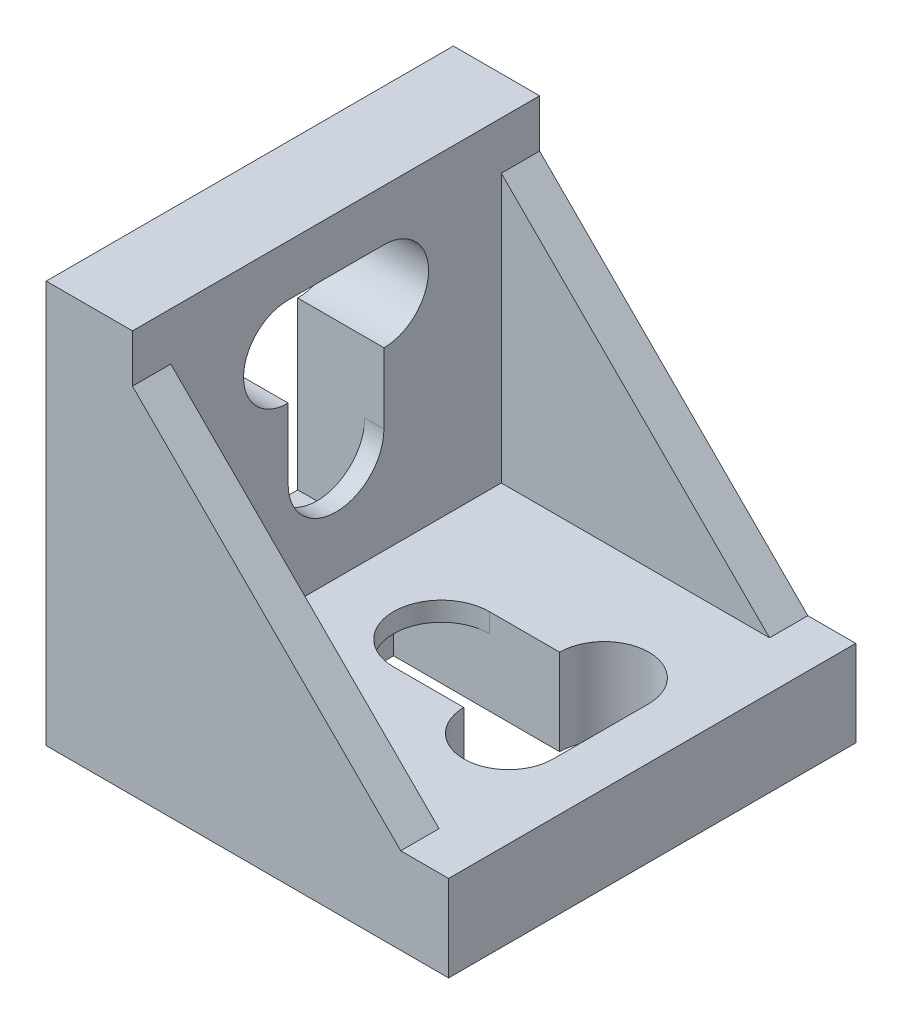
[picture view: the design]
ISO-10303-21;
HEADER;
FILE_DESCRIPTION(('STEP AP214'),'2;1');
FILE_NAME('part.step','',(''),(''),'','','');
FILE_SCHEMA(('AUTOMOTIVE_DESIGN { 1 0 10303 214 1 1 1 1 }'));
ENDSEC;
DATA;
#1=APPLICATION_CONTEXT('core data for automotive mechanical design processes');
#2=APPLICATION_PROTOCOL_DEFINITION('international standard','automotive_design',2000,#1);
#3=PRODUCT_CONTEXT('',#1,'mechanical');
#4=PRODUCT('Part','Part','',(#3));
#5=PRODUCT_RELATED_PRODUCT_CATEGORY('part','',(#4));
#6=PRODUCT_DEFINITION_FORMATION('','',#4);
#7=PRODUCT_DEFINITION_CONTEXT('part definition',#1,'design');
#8=PRODUCT_DEFINITION('design','',#6,#7);
#9=PRODUCT_DEFINITION_SHAPE('','',#8);
#10=(LENGTH_UNIT() NAMED_UNIT(*) SI_UNIT(.MILLI.,.METRE.));
#11=(NAMED_UNIT(*) PLANE_ANGLE_UNIT() SI_UNIT($,.RADIAN.));
#12=(NAMED_UNIT(*) SI_UNIT($,.STERADIAN.) SOLID_ANGLE_UNIT());
#13=UNCERTAINTY_MEASURE_WITH_UNIT(LENGTH_MEASURE(1.E-05),#10,'distance_accuracy_value','');
#14=(GEOMETRIC_REPRESENTATION_CONTEXT(3) GLOBAL_UNCERTAINTY_ASSIGNED_CONTEXT((#13)) GLOBAL_UNIT_ASSIGNED_CONTEXT((#10,
#11,#12)) REPRESENTATION_CONTEXT('',''));
#15=CARTESIAN_POINT('',(0.,0.,0.));
#16=DIRECTION('',(0.,0.,1.));
#17=DIRECTION('',(1.,0.,0.));
#18=AXIS2_PLACEMENT_3D('',#15,#16,#17);
#19=CARTESIAN_POINT('',(7.,-25.6172349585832,0.));
#20=DIRECTION('',(-1.,0.,0.));
#21=DIRECTION('',(0.,0.,1.));
#22=AXIS2_PLACEMENT_3D('',#19,#20,#21);
#23=PLANE('',#22);
#24=DIRECTION('',(0.,-1.,0.));
#25=VECTOR('',#24,1.);
#26=CARTESIAN_POINT('',(7.,-25.6172349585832,-18.25));
#27=LINE('',#26,#25);
#28=CARTESIAN_POINT('',(7.,40.,-18.25));
#29=VERTEX_POINT('',#28);
#30=CARTESIAN_POINT('',(7.,8.33885131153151,-18.25));
#31=VERTEX_POINT('',#30);
#32=EDGE_CURVE('E581',#29,#31,#27,.T.);
#33=ORIENTED_EDGE('',*,*,#32,.T.);
#34=DIRECTION('',(0.,0.,1.));
#35=VECTOR('',#34,1.);
#36=CARTESIAN_POINT('',(7.,8.33885131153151,-24.3860623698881));
#37=LINE('',#36,#35);
#38=CARTESIAN_POINT('',(7.,8.33885131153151,-8.75));
#39=VERTEX_POINT('',#38);
#40=EDGE_CURVE('E574',#31,#39,#37,.T.);
#41=ORIENTED_EDGE('',*,*,#40,.T.);
#42=DIRECTION('',(0.,1.,0.));
#43=VECTOR('',#42,1.);
#44=CARTESIAN_POINT('',(7.,-25.6172349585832,-8.75));
#45=LINE('',#44,#43);
#46=CARTESIAN_POINT('',(7.,25.5048094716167,-8.75));
#47=VERTEX_POINT('',#46);
#48=EDGE_CURVE('E578',#39,#47,#45,.T.);
#49=ORIENTED_EDGE('',*,*,#48,.T.);
#50=CARTESIAN_POINT('',(7.,32.,-5.));
#51=DIRECTION('',(-1.,0.,0.));
#52=DIRECTION('',(0.,0.,1.));
#53=AXIS2_PLACEMENT_3D('',#50,#51,#52);
#54=CIRCLE('',#53,7.5);
#55=CARTESIAN_POINT('',(7.,38.4951905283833,-8.75));
#56=VERTEX_POINT('',#55);
#57=EDGE_CURVE('E610',#56,#47,#54,.T.);
#58=ORIENTED_EDGE('',*,*,#57,.F.);
#59=DIRECTION('',(0.,-1.,0.));
#60=VECTOR('',#59,1.);
#61=CARTESIAN_POINT('',(7.,-25.6172349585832,-8.74999999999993));
#62=LINE('',#61,#60);
#63=CARTESIAN_POINT('',(7.,40.,-8.75));
#64=VERTEX_POINT('',#63);
#65=EDGE_CURVE('E809',#64,#56,#62,.T.);
#66=ORIENTED_EDGE('',*,*,#65,.F.);
#67=DIRECTION('',(0.,0.,1.));
#68=VECTOR('',#67,1.);
#69=CARTESIAN_POINT('',(7.,40.,0.));
#70=LINE('',#69,#68);
#71=EDGE_CURVE('E592',#29,#64,#70,.T.);
#72=ORIENTED_EDGE('',*,*,#71,.F.);
#73=EDGE_LOOP('',(#33,#41,#49,#58,#66,#72));
#74=FACE_BOUND('',#73,.T.);
#75=ADVANCED_FACE('F35',(#74),#23,.T.);
#76=CARTESIAN_POINT('',(7.,-25.6172349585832,-8.75));
#77=DIRECTION('',(0.,0.,1.));
#78=DIRECTION('',(1.,0.,0.));
#79=AXIS2_PLACEMENT_3D('',#76,#77,#78);
#80=PLANE('',#79);
#81=ORIENTED_EDGE('',*,*,#48,.F.);
#82=DIRECTION('',(0.707106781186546,0.707106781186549,0.));
#83=VECTOR('',#82,1.);
#84=CARTESIAN_POINT('',(-9.97804313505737,-8.63919182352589,-8.75));
#85=LINE('',#84,#83);
#86=CARTESIAN_POINT('',(0.,1.3388513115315,-8.75));
#87=VERTEX_POINT('',#86);
#88=EDGE_CURVE('E50',#39,#87,#85,.F.);
#89=ORIENTED_EDGE('',*,*,#88,.T.);
#90=DIRECTION('',(0.,1.,0.));
#91=VECTOR('',#90,1.);
#92=CARTESIAN_POINT('',(0.,-25.6172349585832,-8.75));
#93=LINE('',#92,#91);
#94=CARTESIAN_POINT('',(0.,25.5048094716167,-8.75));
#95=VERTEX_POINT('',#94);
#96=EDGE_CURVE('E608',#87,#95,#93,.T.);
#97=ORIENTED_EDGE('',*,*,#96,.T.);
#98=DIRECTION('',(-1.,0.,0.));
#99=VECTOR('',#98,1.);
#100=CARTESIAN_POINT('',(7.,25.5048094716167,-8.75));
#101=LINE('',#100,#99);
#102=EDGE_CURVE('E586',#47,#95,#101,.T.);
#103=ORIENTED_EDGE('',*,*,#102,.F.);
#104=EDGE_LOOP('',(#81,#89,#97,#103));
#105=FACE_BOUND('',#104,.T.);
#106=ADVANCED_FACE('F584',(#105),#80,.F.);
#107=CARTESIAN_POINT('',(7.,-25.6172349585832,-18.25));
#108=DIRECTION('',(0.,0.,-1.));
#109=DIRECTION('',(0.,1.,0.));
#110=AXIS2_PLACEMENT_3D('',#107,#108,#109);
#111=PLANE('',#110);
#112=DIRECTION('',(-0.707106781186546,-0.707106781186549,0.));
#113=VECTOR('',#112,1.);
#114=CARTESIAN_POINT('',(-9.97804313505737,-8.63919182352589,-18.25));
#115=LINE('',#114,#113);
#116=CARTESIAN_POINT('',(0.,1.3388513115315,-18.25));
#117=VERTEX_POINT('',#116);
#118=EDGE_CURVE('E58',#117,#31,#115,.F.);
#119=ORIENTED_EDGE('',*,*,#118,.T.);
#120=ORIENTED_EDGE('',*,*,#32,.F.);
#121=DIRECTION('',(-1.,0.,0.));
#122=VECTOR('',#121,1.);
#123=CARTESIAN_POINT('',(7.,40.,-18.25));
#124=LINE('',#123,#122);
#125=CARTESIAN_POINT('',(0.,40.,-18.25));
#126=VERTEX_POINT('',#125);
#127=EDGE_CURVE('E613',#29,#126,#124,.T.);
#128=ORIENTED_EDGE('',*,*,#127,.T.);
#129=DIRECTION('',(0.,-1.,0.));
#130=VECTOR('',#129,1.);
#131=CARTESIAN_POINT('',(0.,-25.6172349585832,-18.25));
#132=LINE('',#131,#130);
#133=EDGE_CURVE('E606',#126,#117,#132,.T.);
#134=ORIENTED_EDGE('',*,*,#133,.T.);
#135=EDGE_LOOP('',(#119,#120,#128,#134));
#136=FACE_BOUND('',#135,.T.);
#137=ADVANCED_FACE('F824',(#136),#111,.F.);
#138=CARTESIAN_POINT('',(7.,-25.6172349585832,0.));
#139=DIRECTION('',(-1.,0.,0.));
#140=DIRECTION('',(0.,0.,-1.));
#141=AXIS2_PLACEMENT_3D('',#138,#139,#140);
#142=PLANE('',#141);
#143=DIRECTION('',(0.,1.,0.));
#144=VECTOR('',#143,1.);
#145=CARTESIAN_POINT('',(7.,-25.6172349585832,8.75));
#146=LINE('',#145,#144);
#147=CARTESIAN_POINT('',(7.,8.33885131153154,8.75));
#148=VERTEX_POINT('',#147);
#149=CARTESIAN_POINT('',(7.,25.5048094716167,8.75));
#150=VERTEX_POINT('',#149);
#151=EDGE_CURVE('E549',#148,#150,#146,.T.);
#152=ORIENTED_EDGE('',*,*,#151,.F.);
#153=DIRECTION('',(0.,0.,1.));
#154=VECTOR('',#153,1.);
#155=CARTESIAN_POINT('',(7.,8.33885131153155,2.61393763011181));
#156=LINE('',#155,#154);
#157=CARTESIAN_POINT('',(7.,8.33885131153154,18.25));
#158=VERTEX_POINT('',#157);
#159=EDGE_CURVE('E485',#148,#158,#156,.T.);
#160=ORIENTED_EDGE('',*,*,#159,.T.);
#161=DIRECTION('',(0.,-1.,0.));
#162=VECTOR('',#161,1.);
#163=CARTESIAN_POINT('',(7.,-25.6172349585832,18.25));
#164=LINE('',#163,#162);
#165=CARTESIAN_POINT('',(7.,40.,18.25));
#166=VERTEX_POINT('',#165);
#167=EDGE_CURVE('E565',#166,#158,#164,.T.);
#168=ORIENTED_EDGE('',*,*,#167,.F.);
#169=DIRECTION('',(0.,0.,-1.));
#170=VECTOR('',#169,1.);
#171=CARTESIAN_POINT('',(7.,40.,0.));
#172=LINE('',#171,#170);
#173=CARTESIAN_POINT('',(7.,40.,8.75));
#174=VERTEX_POINT('',#173);
#175=EDGE_CURVE('E787',#166,#174,#172,.T.);
#176=ORIENTED_EDGE('',*,*,#175,.T.);
#177=DIRECTION('',(0.,-1.,0.));
#178=VECTOR('',#177,1.);
#179=CARTESIAN_POINT('',(7.,-25.6172349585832,8.74999999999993));
#180=LINE('',#179,#178);
#181=CARTESIAN_POINT('',(7.,38.4951905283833,8.75));
#182=VERTEX_POINT('',#181);
#183=EDGE_CURVE('E790',#174,#182,#180,.T.);
#184=ORIENTED_EDGE('',*,*,#183,.T.);
#185=CARTESIAN_POINT('',(7.,32.,5.));
#186=DIRECTION('',(1.,0.,0.));
#187=DIRECTION('',(0.,0.,-1.));
#188=AXIS2_PLACEMENT_3D('',#185,#186,#187);
#189=CIRCLE('',#188,7.5);
#190=EDGE_CURVE('E564',#182,#150,#189,.T.);
#191=ORIENTED_EDGE('',*,*,#190,.T.);
#192=EDGE_LOOP('',(#152,#160,#168,#176,#184,#191));
#193=FACE_BOUND('',#192,.T.);
#194=ADVANCED_FACE('F559',(#193),#142,.T.);
#195=CARTESIAN_POINT('',(7.,-25.6172349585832,18.25));
#196=DIRECTION('',(0.,0.,-1.));
#197=DIRECTION('',(0.,1.,0.));
#198=AXIS2_PLACEMENT_3D('',#195,#196,#197);
#199=PLANE('',#198);
#200=ORIENTED_EDGE('',*,*,#167,.T.);
#201=DIRECTION('',(-0.707106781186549,-0.707106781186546,0.));
#202=VECTOR('',#201,1.);
#203=CARTESIAN_POINT('',(0.,1.33885131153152,18.25));
#204=LINE('',#203,#202);
#205=CARTESIAN_POINT('',(0.,1.33885131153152,18.25));
#206=VERTEX_POINT('',#205);
#207=EDGE_CURVE('E11',#158,#206,#204,.T.);
#208=ORIENTED_EDGE('',*,*,#207,.T.);
#209=DIRECTION('',(0.,-1.,0.));
#210=VECTOR('',#209,1.);
#211=CARTESIAN_POINT('',(0.,-25.6172349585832,18.25));
#212=LINE('',#211,#210);
#213=CARTESIAN_POINT('',(0.,40.,18.25));
#214=VERTEX_POINT('',#213);
#215=EDGE_CURVE('E795',#214,#206,#212,.T.);
#216=ORIENTED_EDGE('',*,*,#215,.F.);
#217=DIRECTION('',(-1.,0.,0.));
#218=VECTOR('',#217,1.);
#219=CARTESIAN_POINT('',(7.,40.,18.25));
#220=LINE('',#219,#218);
#221=EDGE_CURVE('E805',#166,#214,#220,.T.);
#222=ORIENTED_EDGE('',*,*,#221,.F.);
#223=EDGE_LOOP('',(#200,#208,#216,#222));
#224=FACE_BOUND('',#223,.T.);
#225=ADVANCED_FACE('F832',(#224),#199,.T.);
#226=CARTESIAN_POINT('',(7.,-25.6172349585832,8.75));
#227=DIRECTION('',(0.,0.,1.));
#228=DIRECTION('',(1.,0.,0.));
#229=AXIS2_PLACEMENT_3D('',#226,#227,#228);
#230=PLANE('',#229);
#231=DIRECTION('',(0.707106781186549,0.707106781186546,0.));
#232=VECTOR('',#231,1.);
#233=CARTESIAN_POINT('',(0.,1.33885131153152,8.75));
#234=LINE('',#233,#232);
#235=CARTESIAN_POINT('',(0.,1.33885131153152,8.75));
#236=VERTEX_POINT('',#235);
#237=EDGE_CURVE('E43',#236,#148,#234,.T.);
#238=ORIENTED_EDGE('',*,*,#237,.T.);
#239=ORIENTED_EDGE('',*,*,#151,.T.);
#240=DIRECTION('',(-1.,0.,0.));
#241=VECTOR('',#240,1.);
#242=CARTESIAN_POINT('',(7.,25.5048094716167,8.75));
#243=LINE('',#242,#241);
#244=CARTESIAN_POINT('',(0.,25.5048094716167,8.75));
#245=VERTEX_POINT('',#244);
#246=EDGE_CURVE('E792',#150,#245,#243,.T.);
#247=ORIENTED_EDGE('',*,*,#246,.T.);
#248=DIRECTION('',(0.,1.,0.));
#249=VECTOR('',#248,1.);
#250=CARTESIAN_POINT('',(0.,-25.6172349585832,8.75));
#251=LINE('',#250,#249);
#252=EDGE_CURVE('E552',#236,#245,#251,.T.);
#253=ORIENTED_EDGE('',*,*,#252,.F.);
#254=EDGE_LOOP('',(#238,#239,#247,#253));
#255=FACE_BOUND('',#254,.T.);
#256=ADVANCED_FACE('F547',(#255),#230,.T.);
#257=CARTESIAN_POINT('',(42.,0.,21.25));
#258=DIRECTION('',(0.,1.,0.));
#259=DIRECTION('',(-1.,0.,0.));
#260=AXIS2_PLACEMENT_3D('',#257,#258,#259);
#261=PLANE('',#260);
#262=DIRECTION('',(0.,0.,-1.));
#263=VECTOR('',#262,1.);
#264=CARTESIAN_POINT('',(8.11245787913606,0.,-4.9));
#265=LINE('',#264,#263);
#266=CARTESIAN_POINT('',(8.11245787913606,0.,4.9));
#267=VERTEX_POINT('',#266);
#268=CARTESIAN_POINT('',(8.11245787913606,0.,-4.9));
#269=VERTEX_POINT('',#268);
#270=EDGE_CURVE('E484',#267,#269,#265,.T.);
#271=ORIENTED_EDGE('',*,*,#270,.T.);
#272=DIRECTION('',(-1.,0.,0.));
#273=VECTOR('',#272,1.);
#274=CARTESIAN_POINT('',(6.11245787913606,0.,-4.9));
#275=LINE('',#274,#273);
#276=CARTESIAN_POINT('',(6.11245787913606,0.,-4.9));
#277=VERTEX_POINT('',#276);
#278=EDGE_CURVE('E457',#269,#277,#275,.T.);
#279=ORIENTED_EDGE('',*,*,#278,.T.);
#280=DIRECTION('',(0.,0.,1.));
#281=VECTOR('',#280,1.);
#282=CARTESIAN_POINT('',(6.11245787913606,0.,4.9));
#283=LINE('',#282,#281);
#284=CARTESIAN_POINT('',(6.11245787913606,0.,4.9));
#285=VERTEX_POINT('',#284);
#286=EDGE_CURVE('E473',#277,#285,#283,.T.);
#287=ORIENTED_EDGE('',*,*,#286,.T.);
#288=DIRECTION('',(1.,0.,0.));
#289=VECTOR('',#288,1.);
#290=CARTESIAN_POINT('',(8.11245787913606,0.,4.9));
#291=LINE('',#290,#289);
#292=EDGE_CURVE('E487',#285,#267,#291,.T.);
#293=ORIENTED_EDGE('',*,*,#292,.T.);
#294=EDGE_LOOP('',(#271,#279,#287,#293));
#295=FACE_BOUND('',#294,.T.);
#296=DIRECTION('',(0.,0.,-1.));
#297=VECTOR('',#296,1.);
#298=CARTESIAN_POINT('',(38.6562082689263,0.,4.9));
#299=LINE('',#298,#297);
#300=CARTESIAN_POINT('',(38.6562082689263,0.,4.9));
#301=VERTEX_POINT('',#300);
#302=CARTESIAN_POINT('',(38.6562082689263,0.,-4.9));
#303=VERTEX_POINT('',#302);
#304=EDGE_CURVE('E512',#301,#303,#299,.T.);
#305=ORIENTED_EDGE('',*,*,#304,.T.);
#306=DIRECTION('',(-1.,0.,0.));
#307=VECTOR('',#306,1.);
#308=CARTESIAN_POINT('',(38.6562082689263,0.,-4.9));
#309=LINE('',#308,#307);
#310=CARTESIAN_POINT('',(36.6562082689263,0.,-4.9));
#311=VERTEX_POINT('',#310);
#312=EDGE_CURVE('E462',#303,#311,#309,.T.);
#313=ORIENTED_EDGE('',*,*,#312,.T.);
#314=DIRECTION('',(0.,0.,-1.));
#315=VECTOR('',#314,1.);
#316=CARTESIAN_POINT('',(36.6562082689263,0.,-5.));
#317=LINE('',#316,#315);
#318=CARTESIAN_POINT('',(36.6562082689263,0.,-5.));
#319=VERTEX_POINT('',#318);
#320=EDGE_CURVE('E923',#311,#319,#317,.T.);
#321=ORIENTED_EDGE('',*,*,#320,.T.);
#322=CARTESIAN_POINT('',(32.,0.,-5.));
#323=DIRECTION('',(0.,1.,0.));
#324=DIRECTION('',(0.,0.,1.));
#325=AXIS2_PLACEMENT_3D('',#322,#323,#324);
#326=CIRCLE('',#325,4.65620826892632);
#327=CARTESIAN_POINT('',(27.3437917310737,0.,-5.));
#328=VERTEX_POINT('',#327);
#329=EDGE_CURVE('E918',#319,#328,#326,.T.);
#330=ORIENTED_EDGE('',*,*,#329,.T.);
#331=DIRECTION('',(-1.,0.,0.));
#332=VECTOR('',#331,1.);
#333=CARTESIAN_POINT('',(30.,0.,-5.));
#334=LINE('',#333,#332);
#335=CARTESIAN_POINT('',(10.,0.,-5.));
#336=VERTEX_POINT('',#335);
#337=EDGE_CURVE('E1839',#328,#336,#334,.T.);
#338=ORIENTED_EDGE('',*,*,#337,.T.);
#339=DIRECTION('',(0.,0.,1.));
#340=VECTOR('',#339,1.);
#341=CARTESIAN_POINT('',(10.,0.,-5.));
#342=LINE('',#341,#340);
#343=CARTESIAN_POINT('',(10.,0.,5.));
#344=VERTEX_POINT('',#343);
#345=EDGE_CURVE('E900',#336,#344,#342,.T.);
#346=ORIENTED_EDGE('',*,*,#345,.T.);
#347=DIRECTION('',(1.,0.,0.));
#348=VECTOR('',#347,1.);
#349=CARTESIAN_POINT('',(30.,0.,5.));
#350=LINE('',#349,#348);
#351=CARTESIAN_POINT('',(27.3437917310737,0.,5.));
#352=VERTEX_POINT('',#351);
#353=EDGE_CURVE('E1844',#344,#352,#350,.T.);
#354=ORIENTED_EDGE('',*,*,#353,.T.);
#355=CARTESIAN_POINT('',(32.,0.,5.));
#356=DIRECTION('',(0.,1.,0.));
#357=DIRECTION('',(0.,0.,1.));
#358=AXIS2_PLACEMENT_3D('',#355,#356,#357);
#359=CIRCLE('',#358,4.65620826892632);
#360=CARTESIAN_POINT('',(36.6562082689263,0.,5.));
#361=VERTEX_POINT('',#360);
#362=EDGE_CURVE('E926',#352,#361,#359,.T.);
#363=ORIENTED_EDGE('',*,*,#362,.T.);
#364=CARTESIAN_POINT('',(36.6562082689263,0.,4.9));
#365=VERTEX_POINT('',#364);
#366=EDGE_CURVE('E932',#361,#365,#317,.T.);
#367=ORIENTED_EDGE('',*,*,#366,.T.);
#368=DIRECTION('',(1.,0.,0.));
#369=VECTOR('',#368,1.);
#370=CARTESIAN_POINT('',(36.6562082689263,0.,4.9));
#371=LINE('',#370,#369);
#372=EDGE_CURVE('E500',#365,#301,#371,.T.);
#373=ORIENTED_EDGE('',*,*,#372,.T.);
#374=EDGE_LOOP('',(#305,#313,#321,#330,#338,#346,#354,#363,#367,#373));
#375=FACE_BOUND('',#374,.T.);
#376=DIRECTION('',(1.,0.,0.));
#377=VECTOR('',#376,1.);
#378=CARTESIAN_POINT('',(42.,0.,-21.25));
#379=LINE('',#378,#377);
#380=CARTESIAN_POINT('',(0.,0.,-21.25));
#381=VERTEX_POINT('',#380);
#382=CARTESIAN_POINT('',(42.,0.,-21.25));
#383=VERTEX_POINT('',#382);
#384=EDGE_CURVE('E682',#381,#383,#379,.T.);
#385=ORIENTED_EDGE('',*,*,#384,.T.);
#386=DIRECTION('',(0.,0.,-1.));
#387=VECTOR('',#386,1.);
#388=CARTESIAN_POINT('',(42.,0.,21.25));
#389=LINE('',#388,#387);
#390=CARTESIAN_POINT('',(42.,0.,21.25));
#391=VERTEX_POINT('',#390);
#392=EDGE_CURVE('E657',#391,#383,#389,.T.);
#393=ORIENTED_EDGE('',*,*,#392,.F.);
#394=DIRECTION('',(1.,0.,0.));
#395=VECTOR('',#394,1.);
#396=CARTESIAN_POINT('',(42.,0.,21.25));
#397=LINE('',#396,#395);
#398=CARTESIAN_POINT('',(0.,0.,21.25));
#399=VERTEX_POINT('',#398);
#400=EDGE_CURVE('E696',#399,#391,#397,.T.);
#401=ORIENTED_EDGE('',*,*,#400,.F.);
#402=DIRECTION('',(0.,0.,-1.));
#403=VECTOR('',#402,1.);
#404=CARTESIAN_POINT('',(0.,0.,21.25));
#405=LINE('',#404,#403);
#406=EDGE_CURVE('E653',#399,#381,#405,.T.);
#407=ORIENTED_EDGE('',*,*,#406,.T.);
#408=EDGE_LOOP('',(#385,#393,#401,#407));
#409=FACE_BOUND('',#408,.T.);
#410=DIRECTION('',(0.,0.,1.));
#411=VECTOR('',#410,1.);
#412=CARTESIAN_POINT('',(1.33885131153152,0.,-8.75));
#413=LINE('',#412,#411);
#414=CARTESIAN_POINT('',(1.33885131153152,0.,-18.25));
#415=VERTEX_POINT('',#414);
#416=CARTESIAN_POINT('',(1.33885131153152,0.,-8.75));
#417=VERTEX_POINT('',#416);
#418=EDGE_CURVE('E520',#415,#417,#413,.T.);
#419=ORIENTED_EDGE('',*,*,#418,.T.);
#420=DIRECTION('',(1.,0.,0.));
#421=VECTOR('',#420,1.);
#422=CARTESIAN_POINT('',(0.,0.,-8.75));
#423=LINE('',#422,#421);
#424=CARTESIAN_POINT('',(25.5048094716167,0.,-8.75));
#425=VERTEX_POINT('',#424);
#426=EDGE_CURVE('E858',#417,#425,#423,.T.);
#427=ORIENTED_EDGE('',*,*,#426,.T.);
#428=CARTESIAN_POINT('',(32.,0.,-5.));
#429=DIRECTION('',(0.,1.,0.));
#430=DIRECTION('',(0.,0.,1.));
#431=AXIS2_PLACEMENT_3D('',#428,#429,#430);
#432=CIRCLE('',#431,7.5);
#433=CARTESIAN_POINT('',(38.4951905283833,0.,-8.75));
#434=VERTEX_POINT('',#433);
#435=EDGE_CURVE('E887',#434,#425,#432,.T.);
#436=ORIENTED_EDGE('',*,*,#435,.F.);
#437=DIRECTION('',(-1.,0.,0.));
#438=VECTOR('',#437,1.);
#439=CARTESIAN_POINT('',(0.,0.,-8.74999999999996));
#440=LINE('',#439,#438);
#441=CARTESIAN_POINT('',(40.,0.,-8.75));
#442=VERTEX_POINT('',#441);
#443=EDGE_CURVE('E895',#442,#434,#440,.T.);
#444=ORIENTED_EDGE('',*,*,#443,.F.);
#445=DIRECTION('',(0.,0.,1.));
#446=VECTOR('',#445,1.);
#447=CARTESIAN_POINT('',(40.,0.,0.));
#448=LINE('',#447,#446);
#449=CARTESIAN_POINT('',(40.,0.,-18.25));
#450=VERTEX_POINT('',#449);
#451=EDGE_CURVE('E892',#450,#442,#448,.T.);
#452=ORIENTED_EDGE('',*,*,#451,.F.);
#453=DIRECTION('',(-1.,0.,0.));
#454=VECTOR('',#453,1.);
#455=CARTESIAN_POINT('',(0.,0.,-18.25));
#456=LINE('',#455,#454);
#457=EDGE_CURVE('E874',#450,#415,#456,.T.);
#458=ORIENTED_EDGE('',*,*,#457,.T.);
#459=EDGE_LOOP('',(#419,#427,#436,#444,#452,#458));
#460=FACE_BOUND('',#459,.T.);
#461=DIRECTION('',(1.,0.,0.));
#462=VECTOR('',#461,1.);
#463=CARTESIAN_POINT('',(0.,0.,8.75));
#464=LINE('',#463,#462);
#465=CARTESIAN_POINT('',(1.3388513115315,0.,8.75));
#466=VERTEX_POINT('',#465);
#467=CARTESIAN_POINT('',(25.5048094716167,0.,8.75));
#468=VERTEX_POINT('',#467);
#469=EDGE_CURVE('E1791',#466,#468,#464,.T.);
#470=ORIENTED_EDGE('',*,*,#469,.F.);
#471=DIRECTION('',(0.,0.,1.));
#472=VECTOR('',#471,1.);
#473=CARTESIAN_POINT('',(1.3388513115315,0.,21.25));
#474=LINE('',#473,#472);
#475=CARTESIAN_POINT('',(1.3388513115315,0.,18.25));
#476=VERTEX_POINT('',#475);
#477=EDGE_CURVE('E529',#466,#476,#474,.T.);
#478=ORIENTED_EDGE('',*,*,#477,.T.);
#479=DIRECTION('',(-1.,0.,0.));
#480=VECTOR('',#479,1.);
#481=CARTESIAN_POINT('',(0.,0.,18.25));
#482=LINE('',#481,#480);
#483=CARTESIAN_POINT('',(40.,0.,18.25));
#484=VERTEX_POINT('',#483);
#485=EDGE_CURVE('E1789',#484,#476,#482,.T.);
#486=ORIENTED_EDGE('',*,*,#485,.F.);
#487=DIRECTION('',(0.,0.,-1.));
#488=VECTOR('',#487,1.);
#489=CARTESIAN_POINT('',(40.,0.,0.));
#490=LINE('',#489,#488);
#491=CARTESIAN_POINT('',(40.,0.,8.75));
#492=VERTEX_POINT('',#491);
#493=EDGE_CURVE('E1786',#484,#492,#490,.T.);
#494=ORIENTED_EDGE('',*,*,#493,.T.);
#495=DIRECTION('',(-1.,0.,0.));
#496=VECTOR('',#495,1.);
#497=CARTESIAN_POINT('',(0.,0.,8.74999999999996));
#498=LINE('',#497,#496);
#499=CARTESIAN_POINT('',(38.4951905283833,0.,8.75));
#500=VERTEX_POINT('',#499);
#501=EDGE_CURVE('E1782',#492,#500,#498,.T.);
#502=ORIENTED_EDGE('',*,*,#501,.T.);
#503=CARTESIAN_POINT('',(32.,0.,5.));
#504=DIRECTION('',(0.,-1.,0.));
#505=DIRECTION('',(0.,0.,-1.));
#506=AXIS2_PLACEMENT_3D('',#503,#504,#505);
#507=CIRCLE('',#506,7.5);
#508=EDGE_CURVE('E1779',#500,#468,#507,.T.);
#509=ORIENTED_EDGE('',*,*,#508,.T.);
#510=EDGE_LOOP('',(#470,#478,#486,#494,#502,#509));
#511=FACE_BOUND('',#510,.T.);
#512=ADVANCED_FACE('F1053',(#295,#375,#409,#460,#511),#261,.F.);
#513=CARTESIAN_POINT('',(20.,42.,0.));
#514=DIRECTION('',(0.,-1.,0.));
#515=DIRECTION('',(1.,0.,0.));
#516=AXIS2_PLACEMENT_3D('',#513,#514,#515);
#517=CYLINDRICAL_SURFACE('',#516,5.);
#518=DIRECTION('',(0.,-1.,0.));
#519=VECTOR('',#518,1.);
#520=CARTESIAN_POINT('',(20.,42.,5.));
#521=LINE('',#520,#519);
#522=CARTESIAN_POINT('',(20.,9.,5.));
#523=VERTEX_POINT('',#522);
#524=CARTESIAN_POINT('',(20.,7.00000000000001,5.));
#525=VERTEX_POINT('',#524);
#526=EDGE_CURVE('E1843',#523,#525,#521,.T.);
#527=ORIENTED_EDGE('',*,*,#526,.T.);
#528=CARTESIAN_POINT('',(20.,7.00000000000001,0.));
#529=DIRECTION('',(0.,-1.,0.));
#530=DIRECTION('',(1.,0.,0.));
#531=AXIS2_PLACEMENT_3D('',#528,#529,#530);
#532=CIRCLE('',#531,5.);
#533=CARTESIAN_POINT('',(20.,7.00000000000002,-5.));
#534=VERTEX_POINT('',#533);
#535=EDGE_CURVE('E524',#525,#534,#532,.T.);
#536=ORIENTED_EDGE('',*,*,#535,.T.);
#537=DIRECTION('',(0.,-1.,0.));
#538=VECTOR('',#537,1.);
#539=CARTESIAN_POINT('',(20.,42.,-5.));
#540=LINE('',#539,#538);
#541=CARTESIAN_POINT('',(20.,9.00000000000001,-5.));
#542=VERTEX_POINT('',#541);
#543=EDGE_CURVE('E1847',#542,#534,#540,.T.);
#544=ORIENTED_EDGE('',*,*,#543,.F.);
#545=CARTESIAN_POINT('',(20.,9.,0.));
#546=DIRECTION('',(0.,-1.,0.));
#547=DIRECTION('',(0.,0.,-1.));
#548=AXIS2_PLACEMENT_3D('',#545,#546,#547);
#549=CIRCLE('',#548,5.);
#550=EDGE_CURVE('E1857',#542,#523,#549,.F.);
#551=ORIENTED_EDGE('',*,*,#550,.T.);
#552=EDGE_LOOP('',(#527,#536,#544,#551));
#553=FACE_BOUND('',#552,.T.);
#554=ADVANCED_FACE('F1118',(#553),#517,.F.);
#555=CARTESIAN_POINT('',(9.,9.,21.25));
#556=DIRECTION('',(0.,-1.,0.));
#557=DIRECTION('',(0.,0.,-1.));
#558=AXIS2_PLACEMENT_3D('',#555,#556,#557);
#559=PLANE('',#558);
#560=DIRECTION('',(0.,0.,-1.));
#561=VECTOR('',#560,1.);
#562=CARTESIAN_POINT('',(37.,9.,-17.25));
#563=LINE('',#562,#561);
#564=CARTESIAN_POINT('',(37.,9.,-17.25));
#565=VERTEX_POINT('',#564);
#566=CARTESIAN_POINT('',(37.,9.,-21.25));
#567=VERTEX_POINT('',#566);
#568=EDGE_CURVE('E709',#565,#567,#563,.T.);
#569=ORIENTED_EDGE('',*,*,#568,.F.);
#570=DIRECTION('',(1.,0.,0.));
#571=VECTOR('',#570,1.);
#572=CARTESIAN_POINT('',(37.,9.,-17.25));
#573=LINE('',#572,#571);
#574=CARTESIAN_POINT('',(9.,9.,-17.25));
#575=VERTEX_POINT('',#574);
#576=EDGE_CURVE('E719',#575,#565,#573,.T.);
#577=ORIENTED_EDGE('',*,*,#576,.F.);
#578=DIRECTION('',(0.,0.,-1.));
#579=VECTOR('',#578,1.);
#580=CARTESIAN_POINT('',(9.,9.,21.25));
#581=LINE('',#580,#579);
#582=CARTESIAN_POINT('',(9.,9.,17.25));
#583=VERTEX_POINT('',#582);
#584=EDGE_CURVE('E663',#583,#575,#581,.T.);
#585=ORIENTED_EDGE('',*,*,#584,.F.);
#586=DIRECTION('',(1.,0.,0.));
#587=VECTOR('',#586,1.);
#588=CARTESIAN_POINT('',(37.,9.,17.25));
#589=LINE('',#588,#587);
#590=CARTESIAN_POINT('',(37.,9.,17.25));
#591=VERTEX_POINT('',#590);
#592=EDGE_CURVE('E712',#583,#591,#589,.T.);
#593=ORIENTED_EDGE('',*,*,#592,.T.);
#594=DIRECTION('',(0.,0.,1.));
#595=VECTOR('',#594,1.);
#596=CARTESIAN_POINT('',(37.,9.,17.25));
#597=LINE('',#596,#595);
#598=CARTESIAN_POINT('',(37.,9.,21.25));
#599=VERTEX_POINT('',#598);
#600=EDGE_CURVE('E700',#591,#599,#597,.T.);
#601=ORIENTED_EDGE('',*,*,#600,.T.);
#602=DIRECTION('',(-1.,0.,0.));
#603=VECTOR('',#602,1.);
#604=CARTESIAN_POINT('',(9.,9.,21.25));
#605=LINE('',#604,#603);
#606=CARTESIAN_POINT('',(42.,9.,21.25));
#607=VERTEX_POINT('',#606);
#608=EDGE_CURVE('E691',#607,#599,#605,.T.);
#609=ORIENTED_EDGE('',*,*,#608,.F.);
#610=DIRECTION('',(0.,0.,-1.));
#611=VECTOR('',#610,1.);
#612=CARTESIAN_POINT('',(42.,9.,21.25));
#613=LINE('',#612,#611);
#614=CARTESIAN_POINT('',(42.,9.,-21.25));
#615=VERTEX_POINT('',#614);
#616=EDGE_CURVE('E660',#607,#615,#613,.T.);
#617=ORIENTED_EDGE('',*,*,#616,.T.);
#618=DIRECTION('',(-1.,0.,0.));
#619=VECTOR('',#618,1.);
#620=CARTESIAN_POINT('',(9.,9.,-21.25));
#621=LINE('',#620,#619);
#622=EDGE_CURVE('E678',#615,#567,#621,.T.);
#623=ORIENTED_EDGE('',*,*,#622,.T.);
#624=EDGE_LOOP('',(#569,#577,#585,#593,#601,#609,#617,#623));
#625=FACE_BOUND('',#624,.T.);
#626=CARTESIAN_POINT('',(32.,9.,-5.));
#627=DIRECTION('',(0.,-1.,0.));
#628=DIRECTION('',(0.,0.,-1.));
#629=AXIS2_PLACEMENT_3D('',#626,#627,#628);
#630=CIRCLE('',#629,4.65620826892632);
#631=CARTESIAN_POINT('',(36.6562082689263,9.,-5.));
#632=VERTEX_POINT('',#631);
#633=CARTESIAN_POINT('',(27.3437917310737,9.00000000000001,-5.));
#634=VERTEX_POINT('',#633);
#635=EDGE_CURVE('E1905',#632,#634,#630,.F.);
#636=ORIENTED_EDGE('',*,*,#635,.F.);
#637=DIRECTION('',(0.,0.,-1.));
#638=VECTOR('',#637,1.);
#639=CARTESIAN_POINT('',(36.6562082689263,9.,21.25));
#640=LINE('',#639,#638);
#641=CARTESIAN_POINT('',(36.6562082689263,9.,5.));
#642=VERTEX_POINT('',#641);
#643=EDGE_CURVE('E1832',#642,#632,#640,.T.);
#644=ORIENTED_EDGE('',*,*,#643,.F.);
#645=CARTESIAN_POINT('',(32.,9.,5.));
#646=DIRECTION('',(0.,-1.,0.));
#647=DIRECTION('',(0.,0.,-1.));
#648=AXIS2_PLACEMENT_3D('',#645,#646,#647);
#649=CIRCLE('',#648,4.65620826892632);
#650=CARTESIAN_POINT('',(27.3437917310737,9.00000000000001,5.));
#651=VERTEX_POINT('',#650);
#652=EDGE_CURVE('E1894',#651,#642,#649,.F.);
#653=ORIENTED_EDGE('',*,*,#652,.F.);
#654=DIRECTION('',(1.,0.,0.));
#655=VECTOR('',#654,1.);
#656=CARTESIAN_POINT('',(9.,9.,5.));
#657=LINE('',#656,#655);
#658=EDGE_CURVE('E1853',#523,#651,#657,.T.);
#659=ORIENTED_EDGE('',*,*,#658,.F.);
#660=ORIENTED_EDGE('',*,*,#550,.F.);
#661=DIRECTION('',(-1.,0.,0.));
#662=VECTOR('',#661,1.);
#663=CARTESIAN_POINT('',(9.,9.,-5.));
#664=LINE('',#663,#662);
#665=EDGE_CURVE('E1860',#634,#542,#664,.T.);
#666=ORIENTED_EDGE('',*,*,#665,.F.);
#667=EDGE_LOOP('',(#636,#644,#653,#659,#660,#666));
#668=FACE_BOUND('',#667,.T.);
#669=ADVANCED_FACE('F1093',(#625,#668),#559,.F.);
#670=CARTESIAN_POINT('',(30.,42.,-5.));
#671=DIRECTION('',(0.,0.,1.));
#672=DIRECTION('',(1.,0.,0.));
#673=AXIS2_PLACEMENT_3D('',#670,#671,#672);
#674=PLANE('',#673);
#675=DIRECTION('',(0.,-1.,0.));
#676=VECTOR('',#675,1.);
#677=CARTESIAN_POINT('',(10.,7.,-5.));
#678=LINE('',#677,#676);
#679=CARTESIAN_POINT('',(10.,7.,-5.));
#680=VERTEX_POINT('',#679);
#681=EDGE_CURVE('E915',#680,#336,#678,.T.);
#682=ORIENTED_EDGE('',*,*,#681,.T.);
#683=ORIENTED_EDGE('',*,*,#337,.F.);
#684=DIRECTION('',(0.,-1.,0.));
#685=VECTOR('',#684,1.);
#686=CARTESIAN_POINT('',(27.3437917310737,42.,-5.));
#687=LINE('',#686,#685);
#688=EDGE_CURVE('E1837',#634,#328,#687,.T.);
#689=ORIENTED_EDGE('',*,*,#688,.F.);
#690=ORIENTED_EDGE('',*,*,#665,.T.);
#691=ORIENTED_EDGE('',*,*,#543,.T.);
#692=DIRECTION('',(-1.,0.,0.));
#693=VECTOR('',#692,1.);
#694=CARTESIAN_POINT('',(23.6718958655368,7.00000000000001,-5.));
#695=LINE('',#694,#693);
#696=EDGE_CURVE('E910',#534,#680,#695,.T.);
#697=ORIENTED_EDGE('',*,*,#696,.T.);
#698=EDGE_LOOP('',(#682,#683,#689,#690,#691,#697));
#699=FACE_BOUND('',#698,.T.);
#700=ADVANCED_FACE('F1428',(#699),#674,.T.);
#701=CARTESIAN_POINT('',(30.,42.,5.));
#702=DIRECTION('',(0.,0.,-1.));
#703=DIRECTION('',(-1.,0.,0.));
#704=AXIS2_PLACEMENT_3D('',#701,#702,#703);
#705=PLANE('',#704);
#706=DIRECTION('',(0.,-1.,0.));
#707=VECTOR('',#706,1.);
#708=CARTESIAN_POINT('',(27.3437917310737,42.,5.));
#709=LINE('',#708,#707);
#710=EDGE_CURVE('E656',#651,#352,#709,.T.);
#711=ORIENTED_EDGE('',*,*,#710,.T.);
#712=ORIENTED_EDGE('',*,*,#353,.F.);
#713=DIRECTION('',(0.,-1.,0.));
#714=VECTOR('',#713,1.);
#715=CARTESIAN_POINT('',(10.,7.,5.));
#716=LINE('',#715,#714);
#717=CARTESIAN_POINT('',(10.,7.,5.));
#718=VERTEX_POINT('',#717);
#719=EDGE_CURVE('E912',#718,#344,#716,.T.);
#720=ORIENTED_EDGE('',*,*,#719,.F.);
#721=DIRECTION('',(1.,0.,0.));
#722=VECTOR('',#721,1.);
#723=CARTESIAN_POINT('',(10.,7.,5.));
#724=LINE('',#723,#722);
#725=EDGE_CURVE('E905',#718,#525,#724,.T.);
#726=ORIENTED_EDGE('',*,*,#725,.T.);
#727=ORIENTED_EDGE('',*,*,#526,.F.);
#728=ORIENTED_EDGE('',*,*,#658,.T.);
#729=EDGE_LOOP('',(#711,#712,#720,#726,#727,#728));
#730=FACE_BOUND('',#729,.T.);
#731=ADVANCED_FACE('F1063',(#730),#705,.T.);
#732=CARTESIAN_POINT('',(0.,0.,21.25));
#733=DIRECTION('',(1.,0.,0.));
#734=DIRECTION('',(0.,0.,-1.));
#735=AXIS2_PLACEMENT_3D('',#732,#733,#734);
#736=PLANE('',#735);
#737=DIRECTION('',(0.,-1.,0.));
#738=VECTOR('',#737,1.);
#739=CARTESIAN_POINT('',(0.,38.6562082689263,-4.9));
#740=LINE('',#739,#738);
#741=CARTESIAN_POINT('',(0.,38.6562082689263,-4.9));
#742=VERTEX_POINT('',#741);
#743=CARTESIAN_POINT('',(0.,36.6562082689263,-4.9));
#744=VERTEX_POINT('',#743);
#745=EDGE_CURVE('E946',#742,#744,#740,.T.);
#746=ORIENTED_EDGE('',*,*,#745,.F.);
#747=DIRECTION('',(0.,0.,-1.));
#748=VECTOR('',#747,1.);
#749=CARTESIAN_POINT('',(0.,38.6562082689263,4.9));
#750=LINE('',#749,#748);
#751=CARTESIAN_POINT('',(0.,38.6562082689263,4.9));
#752=VERTEX_POINT('',#751);
#753=EDGE_CURVE('E950',#752,#742,#750,.T.);
#754=ORIENTED_EDGE('',*,*,#753,.F.);
#755=DIRECTION('',(0.,1.,0.));
#756=VECTOR('',#755,1.);
#757=CARTESIAN_POINT('',(0.,36.6562082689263,4.9));
#758=LINE('',#757,#756);
#759=CARTESIAN_POINT('',(0.,36.6562082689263,4.9));
#760=VERTEX_POINT('',#759);
#761=EDGE_CURVE('E972',#760,#752,#758,.T.);
#762=ORIENTED_EDGE('',*,*,#761,.F.);
#763=DIRECTION('',(0.,0.,-1.));
#764=VECTOR('',#763,1.);
#765=CARTESIAN_POINT('',(0.,36.6562082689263,-5.));
#766=LINE('',#765,#764);
#767=CARTESIAN_POINT('',(0.,36.6562082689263,5.));
#768=VERTEX_POINT('',#767);
#769=EDGE_CURVE('E649',#768,#760,#766,.T.);
#770=ORIENTED_EDGE('',*,*,#769,.F.);
#771=CARTESIAN_POINT('',(0.,32.,5.));
#772=DIRECTION('',(-1.,0.,0.));
#773=DIRECTION('',(0.,0.,1.));
#774=AXIS2_PLACEMENT_3D('',#771,#772,#773);
#775=CIRCLE('',#774,4.65620826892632);
#776=CARTESIAN_POINT('',(0.,27.3437917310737,5.));
#777=VERTEX_POINT('',#776);
#778=EDGE_CURVE('E637',#777,#768,#775,.T.);
#779=ORIENTED_EDGE('',*,*,#778,.F.);
#780=DIRECTION('',(0.,1.,0.));
#781=VECTOR('',#780,1.);
#782=CARTESIAN_POINT('',(0.,30.,5.));
#783=LINE('',#782,#781);
#784=CARTESIAN_POINT('',(0.,10.,5.));
#785=VERTEX_POINT('',#784);
#786=EDGE_CURVE('E617',#785,#777,#783,.T.);
#787=ORIENTED_EDGE('',*,*,#786,.F.);
#788=DIRECTION('',(0.,0.,1.));
#789=VECTOR('',#788,1.);
#790=CARTESIAN_POINT('',(0.,10.,-5.));
#791=LINE('',#790,#789);
#792=CARTESIAN_POINT('',(0.,10.,-5.));
#793=VERTEX_POINT('',#792);
#794=EDGE_CURVE('E761',#793,#785,#791,.T.);
#795=ORIENTED_EDGE('',*,*,#794,.F.);
#796=DIRECTION('',(0.,-1.,0.));
#797=VECTOR('',#796,1.);
#798=CARTESIAN_POINT('',(0.,30.,-5.));
#799=LINE('',#798,#797);
#800=CARTESIAN_POINT('',(0.,27.3437917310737,-5.));
#801=VERTEX_POINT('',#800);
#802=EDGE_CURVE('E612',#801,#793,#799,.T.);
#803=ORIENTED_EDGE('',*,*,#802,.F.);
#804=CARTESIAN_POINT('',(0.,32.,-5.));
#805=DIRECTION('',(-1.,0.,0.));
#806=DIRECTION('',(0.,0.,1.));
#807=AXIS2_PLACEMENT_3D('',#804,#805,#806);
#808=CIRCLE('',#807,4.65620826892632);
#809=CARTESIAN_POINT('',(0.,36.6562082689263,-5.));
#810=VERTEX_POINT('',#809);
#811=EDGE_CURVE('E634',#810,#801,#808,.T.);
#812=ORIENTED_EDGE('',*,*,#811,.F.);
#813=EDGE_CURVE('E640',#744,#810,#766,.T.);
#814=ORIENTED_EDGE('',*,*,#813,.F.);
#815=EDGE_LOOP('',(#746,#754,#762,#770,#779,#787,#795,#803,#812,#814));
#816=FACE_BOUND('',#815,.T.);
#817=DIRECTION('',(0.,0.,-1.));
#818=VECTOR('',#817,1.);
#819=CARTESIAN_POINT('',(0.,1.33885131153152,8.75));
#820=LINE('',#819,#818);
#821=EDGE_CURVE('E542',#206,#236,#820,.T.);
#822=ORIENTED_EDGE('',*,*,#821,.T.);
#823=ORIENTED_EDGE('',*,*,#252,.T.);
#824=CARTESIAN_POINT('',(0.,32.,5.));
#825=DIRECTION('',(1.,0.,0.));
#826=DIRECTION('',(0.,0.,-1.));
#827=AXIS2_PLACEMENT_3D('',#824,#825,#826);
#828=CIRCLE('',#827,7.5);
#829=CARTESIAN_POINT('',(0.,38.4951905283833,8.75));
#830=VERTEX_POINT('',#829);
#831=EDGE_CURVE('E783',#830,#245,#828,.T.);
#832=ORIENTED_EDGE('',*,*,#831,.F.);
#833=DIRECTION('',(0.,-1.,0.));
#834=VECTOR('',#833,1.);
#835=CARTESIAN_POINT('',(0.,-25.6172349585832,8.74999999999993));
#836=LINE('',#835,#834);
#837=CARTESIAN_POINT('',(0.,40.,8.75));
#838=VERTEX_POINT('',#837);
#839=EDGE_CURVE('E784',#838,#830,#836,.T.);
#840=ORIENTED_EDGE('',*,*,#839,.F.);
#841=DIRECTION('',(0.,0.,-1.));
#842=VECTOR('',#841,1.);
#843=CARTESIAN_POINT('',(0.,40.,0.));
#844=LINE('',#843,#842);
#845=EDGE_CURVE('E797',#214,#838,#844,.T.);
#846=ORIENTED_EDGE('',*,*,#845,.F.);
#847=ORIENTED_EDGE('',*,*,#215,.T.);
#848=EDGE_LOOP('',(#822,#823,#832,#840,#846,#847));
#849=FACE_BOUND('',#848,.T.);
#850=DIRECTION('',(0.,-1.,0.));
#851=VECTOR('',#850,1.);
#852=CARTESIAN_POINT('',(0.,0.,-21.25));
#853=LINE('',#852,#851);
#854=CARTESIAN_POINT('',(0.,42.,-21.25));
#855=VERTEX_POINT('',#854);
#856=EDGE_CURVE('E684',#855,#381,#853,.T.);
#857=ORIENTED_EDGE('',*,*,#856,.T.);
#858=ORIENTED_EDGE('',*,*,#406,.F.);
#859=DIRECTION('',(0.,-1.,0.));
#860=VECTOR('',#859,1.);
#861=CARTESIAN_POINT('',(0.,0.,21.25));
#862=LINE('',#861,#860);
#863=CARTESIAN_POINT('',(0.,42.,21.25));
#864=VERTEX_POINT('',#863);
#865=EDGE_CURVE('E675',#864,#399,#862,.T.);
#866=ORIENTED_EDGE('',*,*,#865,.F.);
#867=DIRECTION('',(0.,0.,-1.));
#868=VECTOR('',#867,1.);
#869=CARTESIAN_POINT('',(0.,42.,21.25));
#870=LINE('',#869,#868);
#871=EDGE_CURVE('E669',#864,#855,#870,.T.);
#872=ORIENTED_EDGE('',*,*,#871,.T.);
#873=EDGE_LOOP('',(#857,#858,#866,#872));
#874=FACE_BOUND('',#873,.T.);
#875=ORIENTED_EDGE('',*,*,#96,.F.);
#876=DIRECTION('',(0.,0.,-1.));
#877=VECTOR('',#876,1.);
#878=CARTESIAN_POINT('',(0.,1.3388513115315,21.25));
#879=LINE('',#878,#877);
#880=EDGE_CURVE('E537',#87,#117,#879,.T.);
#881=ORIENTED_EDGE('',*,*,#880,.T.);
#882=ORIENTED_EDGE('',*,*,#133,.F.);
#883=DIRECTION('',(0.,0.,1.));
#884=VECTOR('',#883,1.);
#885=CARTESIAN_POINT('',(0.,40.,0.));
#886=LINE('',#885,#884);
#887=CARTESIAN_POINT('',(0.,40.,-8.75));
#888=VERTEX_POINT('',#887);
#889=EDGE_CURVE('E603',#126,#888,#886,.T.);
#890=ORIENTED_EDGE('',*,*,#889,.T.);
#891=DIRECTION('',(0.,-1.,0.));
#892=VECTOR('',#891,1.);
#893=CARTESIAN_POINT('',(0.,-25.6172349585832,-8.74999999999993));
#894=LINE('',#893,#892);
#895=CARTESIAN_POINT('',(0.,38.4951905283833,-8.75));
#896=VERTEX_POINT('',#895);
#897=EDGE_CURVE('E599',#888,#896,#894,.T.);
#898=ORIENTED_EDGE('',*,*,#897,.T.);
#899=CARTESIAN_POINT('',(0.,32.,-5.));
#900=DIRECTION('',(-1.,0.,0.));
#901=DIRECTION('',(0.,0.,1.));
#902=AXIS2_PLACEMENT_3D('',#899,#900,#901);
#903=CIRCLE('',#902,7.5);
#904=EDGE_CURVE('E596',#896,#95,#903,.T.);
#905=ORIENTED_EDGE('',*,*,#904,.T.);
#906=EDGE_LOOP('',(#875,#881,#882,#890,#898,#905));
#907=FACE_BOUND('',#906,.T.);
#908=DIRECTION('',(0.,-1.,0.));
#909=VECTOR('',#908,1.);
#910=CARTESIAN_POINT('',(0.,6.11245787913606,-4.9));
#911=LINE('',#910,#909);
#912=CARTESIAN_POINT('',(0.,8.11245787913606,-4.9));
#913=VERTEX_POINT('',#912);
#914=CARTESIAN_POINT('',(0.,6.11245787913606,-4.9));
#915=VERTEX_POINT('',#914);
#916=EDGE_CURVE('E1862',#913,#915,#911,.T.);
#917=ORIENTED_EDGE('',*,*,#916,.F.);
#918=DIRECTION('',(0.,0.,-1.));
#919=VECTOR('',#918,1.);
#920=CARTESIAN_POINT('',(0.,8.11245787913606,-4.9));
#921=LINE('',#920,#919);
#922=CARTESIAN_POINT('',(0.,8.11245787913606,4.9));
#923=VERTEX_POINT('',#922);
#924=EDGE_CURVE('E1867',#923,#913,#921,.T.);
#925=ORIENTED_EDGE('',*,*,#924,.F.);
#926=DIRECTION('',(0.,1.,0.));
#927=VECTOR('',#926,1.);
#928=CARTESIAN_POINT('',(0.,8.11245787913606,4.9));
#929=LINE('',#928,#927);
#930=CARTESIAN_POINT('',(0.,6.11245787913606,4.9));
#931=VERTEX_POINT('',#930);
#932=EDGE_CURVE('E1877',#931,#923,#929,.T.);
#933=ORIENTED_EDGE('',*,*,#932,.F.);
#934=DIRECTION('',(0.,0.,1.));
#935=VECTOR('',#934,1.);
#936=CARTESIAN_POINT('',(0.,6.11245787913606,4.9));
#937=LINE('',#936,#935);
#938=EDGE_CURVE('E1875',#915,#931,#937,.T.);
#939=ORIENTED_EDGE('',*,*,#938,.F.);
#940=EDGE_LOOP('',(#917,#925,#933,#939));
#941=FACE_BOUND('',#940,.T.);
#942=ADVANCED_FACE('F756',(#816,#849,#874,#907,#941),#736,.F.);
#943=CARTESIAN_POINT('',(42.,20.,0.));
#944=DIRECTION('',(-1.,0.,0.));
#945=DIRECTION('',(0.,0.,1.));
#946=AXIS2_PLACEMENT_3D('',#943,#944,#945);
#947=CYLINDRICAL_SURFACE('',#946,5.);
#948=CARTESIAN_POINT('',(7.,20.,0.));
#949=DIRECTION('',(-1.,0.,0.));
#950=DIRECTION('',(0.,0.,1.));
#951=AXIS2_PLACEMENT_3D('',#948,#949,#950);
#952=CIRCLE('',#951,5.);
#953=CARTESIAN_POINT('',(7.00000000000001,20.,5.));
#954=VERTEX_POINT('',#953);
#955=CARTESIAN_POINT('',(7.,20.,-5.));
#956=VERTEX_POINT('',#955);
#957=EDGE_CURVE('E777',#954,#956,#952,.F.);
#958=ORIENTED_EDGE('',*,*,#957,.F.);
#959=DIRECTION('',(-1.,0.,0.));
#960=VECTOR('',#959,1.);
#961=CARTESIAN_POINT('',(42.,20.,5.));
#962=LINE('',#961,#960);
#963=CARTESIAN_POINT('',(9.00000000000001,20.,5.));
#964=VERTEX_POINT('',#963);
#965=EDGE_CURVE('E620',#964,#954,#962,.T.);
#966=ORIENTED_EDGE('',*,*,#965,.F.);
#967=CARTESIAN_POINT('',(9.,20.,0.));
#968=DIRECTION('',(-1.,0.,0.));
#969=DIRECTION('',(0.,-1.,0.));
#970=AXIS2_PLACEMENT_3D('',#967,#968,#969);
#971=CIRCLE('',#970,5.);
#972=CARTESIAN_POINT('',(9.00000000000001,20.,-5.));
#973=VERTEX_POINT('',#972);
#974=EDGE_CURVE('E631',#973,#964,#971,.T.);
#975=ORIENTED_EDGE('',*,*,#974,.F.);
#976=DIRECTION('',(-1.,0.,0.));
#977=VECTOR('',#976,1.);
#978=CARTESIAN_POINT('',(42.,20.,-5.));
#979=LINE('',#978,#977);
#980=EDGE_CURVE('E619',#973,#956,#979,.T.);
#981=ORIENTED_EDGE('',*,*,#980,.T.);
#982=EDGE_LOOP('',(#958,#966,#975,#981));
#983=FACE_BOUND('',#982,.T.);
#984=ADVANCED_FACE('F1019',(#983),#947,.F.);
#985=CARTESIAN_POINT('',(9.,42.,21.25));
#986=DIRECTION('',(-1.,0.,0.));
#987=DIRECTION('',(0.,-1.,0.));
#988=AXIS2_PLACEMENT_3D('',#985,#986,#987);
#989=PLANE('',#988);
#990=ORIENTED_EDGE('',*,*,#974,.T.);
#991=DIRECTION('',(0.,1.,0.));
#992=VECTOR('',#991,1.);
#993=CARTESIAN_POINT('',(9.,42.,5.));
#994=LINE('',#993,#992);
#995=CARTESIAN_POINT('',(9.00000000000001,27.3437917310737,5.));
#996=VERTEX_POINT('',#995);
#997=EDGE_CURVE('E628',#964,#996,#994,.T.);
#998=ORIENTED_EDGE('',*,*,#997,.T.);
#999=CARTESIAN_POINT('',(9.,32.,5.));
#1000=DIRECTION('',(-1.,0.,0.));
#1001=DIRECTION('',(0.,-1.,0.));
#1002=AXIS2_PLACEMENT_3D('',#999,#1000,#1001);
#1003=CIRCLE('',#1002,4.65620826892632);
#1004=CARTESIAN_POINT('',(9.00000000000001,36.6562082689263,5.));
#1005=VERTEX_POINT('',#1004);
#1006=EDGE_CURVE('E739',#996,#1005,#1003,.T.);
#1007=ORIENTED_EDGE('',*,*,#1006,.T.);
#1008=DIRECTION('',(0.,0.,-1.));
#1009=VECTOR('',#1008,1.);
#1010=CARTESIAN_POINT('',(9.,36.6562082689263,21.25));
#1011=LINE('',#1010,#1009);
#1012=CARTESIAN_POINT('',(9.00000000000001,36.6562082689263,-5.));
#1013=VERTEX_POINT('',#1012);
#1014=EDGE_CURVE('E736',#1005,#1013,#1011,.T.);
#1015=ORIENTED_EDGE('',*,*,#1014,.T.);
#1016=CARTESIAN_POINT('',(9.,32.,-5.));
#1017=DIRECTION('',(-1.,0.,0.));
#1018=DIRECTION('',(0.,-1.,0.));
#1019=AXIS2_PLACEMENT_3D('',#1016,#1017,#1018);
#1020=CIRCLE('',#1019,4.65620826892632);
#1021=CARTESIAN_POINT('',(9.00000000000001,27.3437917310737,-5.));
#1022=VERTEX_POINT('',#1021);
#1023=EDGE_CURVE('E726',#1013,#1022,#1020,.T.);
#1024=ORIENTED_EDGE('',*,*,#1023,.T.);
#1025=DIRECTION('',(0.,-1.,0.));
#1026=VECTOR('',#1025,1.);
#1027=CARTESIAN_POINT('',(9.,42.,-5.));
#1028=LINE('',#1027,#1026);
#1029=EDGE_CURVE('E623',#1022,#973,#1028,.T.);
#1030=ORIENTED_EDGE('',*,*,#1029,.T.);
#1031=EDGE_LOOP('',(#990,#998,#1007,#1015,#1024,#1030));
#1032=FACE_BOUND('',#1031,.T.);
#1033=DIRECTION('',(0.,0.,-1.));
#1034=VECTOR('',#1033,1.);
#1035=CARTESIAN_POINT('',(9.,37.,-17.25));
#1036=LINE('',#1035,#1034);
#1037=CARTESIAN_POINT('',(9.,37.,-17.25));
#1038=VERTEX_POINT('',#1037);
#1039=CARTESIAN_POINT('',(9.,37.,-21.25));
#1040=VERTEX_POINT('',#1039);
#1041=EDGE_CURVE('E717',#1038,#1040,#1036,.T.);
#1042=ORIENTED_EDGE('',*,*,#1041,.T.);
#1043=DIRECTION('',(0.,1.,0.));
#1044=VECTOR('',#1043,1.);
#1045=CARTESIAN_POINT('',(9.,42.,-21.25));
#1046=LINE('',#1045,#1044);
#1047=CARTESIAN_POINT('',(9.,42.,-21.25));
#1048=VERTEX_POINT('',#1047);
#1049=EDGE_CURVE('E676',#1040,#1048,#1046,.T.);
#1050=ORIENTED_EDGE('',*,*,#1049,.T.);
#1051=DIRECTION('',(0.,0.,-1.));
#1052=VECTOR('',#1051,1.);
#1053=CARTESIAN_POINT('',(9.,42.,21.25));
#1054=LINE('',#1053,#1052);
#1055=CARTESIAN_POINT('',(9.,42.,21.25));
#1056=VERTEX_POINT('',#1055);
#1057=EDGE_CURVE('E666',#1056,#1048,#1054,.T.);
#1058=ORIENTED_EDGE('',*,*,#1057,.F.);
#1059=DIRECTION('',(0.,1.,0.));
#1060=VECTOR('',#1059,1.);
#1061=CARTESIAN_POINT('',(9.,42.,21.25));
#1062=LINE('',#1061,#1060);
#1063=CARTESIAN_POINT('',(9.,37.,21.25));
#1064=VERTEX_POINT('',#1063);
#1065=EDGE_CURVE('E689',#1064,#1056,#1062,.T.);
#1066=ORIENTED_EDGE('',*,*,#1065,.F.);
#1067=DIRECTION('',(0.,0.,1.));
#1068=VECTOR('',#1067,1.);
#1069=CARTESIAN_POINT('',(9.,37.,17.25));
#1070=LINE('',#1069,#1068);
#1071=CARTESIAN_POINT('',(9.,37.,17.25));
#1072=VERTEX_POINT('',#1071);
#1073=EDGE_CURVE('E687',#1072,#1064,#1070,.T.);
#1074=ORIENTED_EDGE('',*,*,#1073,.F.);
#1075=DIRECTION('',(0.,-1.,0.));
#1076=VECTOR('',#1075,1.);
#1077=CARTESIAN_POINT('',(9.,9.,17.25));
#1078=LINE('',#1077,#1076);
#1079=EDGE_CURVE('E708',#1072,#583,#1078,.T.);
#1080=ORIENTED_EDGE('',*,*,#1079,.T.);
#1081=ORIENTED_EDGE('',*,*,#584,.T.);
#1082=DIRECTION('',(0.,-1.,0.));
#1083=VECTOR('',#1082,1.);
#1084=CARTESIAN_POINT('',(9.,9.,-17.25));
#1085=LINE('',#1084,#1083);
#1086=EDGE_CURVE('E725',#1038,#575,#1085,.T.);
#1087=ORIENTED_EDGE('',*,*,#1086,.F.);
#1088=EDGE_LOOP('',(#1042,#1050,#1058,#1066,#1074,#1080,#1081,#1087));
#1089=FACE_BOUND('',#1088,.T.);
#1090=ADVANCED_FACE('F1014',(#1032,#1089),#989,.F.);
#1091=CARTESIAN_POINT('',(42.,9.,21.25));
#1092=DIRECTION('',(-1.,0.,0.));
#1093=DIRECTION('',(0.,0.,1.));
#1094=AXIS2_PLACEMENT_3D('',#1091,#1092,#1093);
#1095=PLANE('',#1094);
#1096=DIRECTION('',(0.,1.,0.));
#1097=VECTOR('',#1096,1.);
#1098=CARTESIAN_POINT('',(42.,9.,-21.25));
#1099=LINE('',#1098,#1097);
#1100=EDGE_CURVE('E680',#383,#615,#1099,.T.);
#1101=ORIENTED_EDGE('',*,*,#1100,.T.);
#1102=ORIENTED_EDGE('',*,*,#616,.F.);
#1103=DIRECTION('',(0.,1.,0.));
#1104=VECTOR('',#1103,1.);
#1105=CARTESIAN_POINT('',(42.,9.,21.25));
#1106=LINE('',#1105,#1104);
#1107=EDGE_CURVE('E694',#391,#607,#1106,.T.);
#1108=ORIENTED_EDGE('',*,*,#1107,.F.);
#1109=ORIENTED_EDGE('',*,*,#392,.T.);
#1110=EDGE_LOOP('',(#1101,#1102,#1108,#1109));
#1111=FACE_BOUND('',#1110,.T.);
#1112=ADVANCED_FACE('F1106',(#1111),#1095,.F.);
#1113=CARTESIAN_POINT('',(0.,42.,21.25));
#1114=DIRECTION('',(0.,-1.,0.));
#1115=DIRECTION('',(0.,0.,-1.));
#1116=AXIS2_PLACEMENT_3D('',#1113,#1114,#1115);
#1117=PLANE('',#1116);
#1118=DIRECTION('',(-1.,0.,0.));
#1119=VECTOR('',#1118,1.);
#1120=CARTESIAN_POINT('',(0.,42.,-21.25));
#1121=LINE('',#1120,#1119);
#1122=EDGE_CURVE('E673',#1048,#855,#1121,.T.);
#1123=ORIENTED_EDGE('',*,*,#1122,.T.);
#1124=ORIENTED_EDGE('',*,*,#871,.F.);
#1125=DIRECTION('',(-1.,0.,0.));
#1126=VECTOR('',#1125,1.);
#1127=CARTESIAN_POINT('',(0.,42.,21.25));
#1128=LINE('',#1127,#1126);
#1129=EDGE_CURVE('E672',#1056,#864,#1128,.T.);
#1130=ORIENTED_EDGE('',*,*,#1129,.F.);
#1131=ORIENTED_EDGE('',*,*,#1057,.T.);
#1132=EDGE_LOOP('',(#1123,#1124,#1130,#1131));
#1133=FACE_BOUND('',#1132,.T.);
#1134=ADVANCED_FACE('F1085',(#1133),#1117,.F.);
#1135=CARTESIAN_POINT('',(0.,42.,21.25));
#1136=DIRECTION('',(0.,0.,-1.));
#1137=DIRECTION('',(-1.,0.,0.));
#1138=AXIS2_PLACEMENT_3D('',#1135,#1136,#1137);
#1139=PLANE('',#1138);
#1140=DIRECTION('',(-0.707106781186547,0.707106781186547,0.));
#1141=VECTOR('',#1140,1.);
#1142=CARTESIAN_POINT('',(9.,37.,21.25));
#1143=LINE('',#1142,#1141);
#1144=EDGE_CURVE('E705',#599,#1064,#1143,.T.);
#1145=ORIENTED_EDGE('',*,*,#1144,.T.);
#1146=ORIENTED_EDGE('',*,*,#1065,.T.);
#1147=ORIENTED_EDGE('',*,*,#1129,.T.);
#1148=ORIENTED_EDGE('',*,*,#865,.T.);
#1149=ORIENTED_EDGE('',*,*,#400,.T.);
#1150=ORIENTED_EDGE('',*,*,#1107,.T.);
#1151=ORIENTED_EDGE('',*,*,#608,.T.);
#1152=EDGE_LOOP('',(#1145,#1146,#1147,#1148,#1149,#1150,#1151));
#1153=FACE_BOUND('',#1152,.T.);
#1154=ADVANCED_FACE('F1080',(#1153),#1139,.F.);
#1155=CARTESIAN_POINT('',(0.,42.,-21.25));
#1156=DIRECTION('',(0.,0.,-1.));
#1157=DIRECTION('',(-1.,0.,0.));
#1158=AXIS2_PLACEMENT_3D('',#1155,#1156,#1157);
#1159=PLANE('',#1158);
#1160=ORIENTED_EDGE('',*,*,#1049,.F.);
#1161=DIRECTION('',(-0.707106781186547,0.707106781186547,0.));
#1162=VECTOR('',#1161,1.);
#1163=CARTESIAN_POINT('',(9.,37.,-21.25));
#1164=LINE('',#1163,#1162);
#1165=EDGE_CURVE('E722',#567,#1040,#1164,.T.);
#1166=ORIENTED_EDGE('',*,*,#1165,.F.);
#1167=ORIENTED_EDGE('',*,*,#622,.F.);
#1168=ORIENTED_EDGE('',*,*,#1100,.F.);
#1169=ORIENTED_EDGE('',*,*,#384,.F.);
#1170=ORIENTED_EDGE('',*,*,#856,.F.);
#1171=ORIENTED_EDGE('',*,*,#1122,.F.);
#1172=EDGE_LOOP('',(#1160,#1166,#1167,#1168,#1169,#1170,#1171));
#1173=FACE_BOUND('',#1172,.T.);
#1174=ADVANCED_FACE('F1072',(#1173),#1159,.T.);
#1175=CARTESIAN_POINT('',(9.,37.,17.25));
#1176=DIRECTION('',(0.707106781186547,0.707106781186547,0.));
#1177=DIRECTION('',(-0.707106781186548,0.707106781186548,0.));
#1178=AXIS2_PLACEMENT_3D('',#1175,#1176,#1177);
#1179=PLANE('',#1178);
#1180=ORIENTED_EDGE('',*,*,#1144,.F.);
#1181=ORIENTED_EDGE('',*,*,#600,.F.);
#1182=DIRECTION('',(-0.707106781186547,0.707106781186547,0.));
#1183=VECTOR('',#1182,1.);
#1184=CARTESIAN_POINT('',(9.,37.,17.25));
#1185=LINE('',#1184,#1183);
#1186=EDGE_CURVE('E703',#591,#1072,#1185,.T.);
#1187=ORIENTED_EDGE('',*,*,#1186,.T.);
#1188=ORIENTED_EDGE('',*,*,#1073,.T.);
#1189=EDGE_LOOP('',(#1180,#1181,#1187,#1188));
#1190=FACE_BOUND('',#1189,.T.);
#1191=ADVANCED_FACE('F1103',(#1190),#1179,.T.);
#1192=CARTESIAN_POINT('',(9.,9.,17.25));
#1193=DIRECTION('',(0.,0.,1.));
#1194=DIRECTION('',(1.,0.,0.));
#1195=AXIS2_PLACEMENT_3D('',#1192,#1193,#1194);
#1196=PLANE('',#1195);
#1197=ORIENTED_EDGE('',*,*,#1079,.F.);
#1198=ORIENTED_EDGE('',*,*,#1186,.F.);
#1199=ORIENTED_EDGE('',*,*,#592,.F.);
#1200=EDGE_LOOP('',(#1197,#1198,#1199));
#1201=FACE_BOUND('',#1200,.T.);
#1202=ADVANCED_FACE('F1101',(#1201),#1196,.F.);
#1203=CARTESIAN_POINT('',(9.,37.,-17.25));
#1204=DIRECTION('',(-0.707106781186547,-0.707106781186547,0.));
#1205=DIRECTION('',(0.707106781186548,-0.707106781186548,0.));
#1206=AXIS2_PLACEMENT_3D('',#1203,#1204,#1205);
#1207=PLANE('',#1206);
#1208=ORIENTED_EDGE('',*,*,#1165,.T.);
#1209=ORIENTED_EDGE('',*,*,#1041,.F.);
#1210=DIRECTION('',(-0.707106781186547,0.707106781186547,0.));
#1211=VECTOR('',#1210,1.);
#1212=CARTESIAN_POINT('',(9.,37.,-17.25));
#1213=LINE('',#1212,#1211);
#1214=EDGE_CURVE('E729',#565,#1038,#1213,.T.);
#1215=ORIENTED_EDGE('',*,*,#1214,.F.);
#1216=ORIENTED_EDGE('',*,*,#568,.T.);
#1217=EDGE_LOOP('',(#1208,#1209,#1215,#1216));
#1218=FACE_BOUND('',#1217,.T.);
#1219=ADVANCED_FACE('F1090',(#1218),#1207,.F.);
#1220=CARTESIAN_POINT('',(9.,9.,-17.25));
#1221=DIRECTION('',(0.,0.,-1.));
#1222=DIRECTION('',(1.,0.,0.));
#1223=AXIS2_PLACEMENT_3D('',#1220,#1221,#1222);
#1224=PLANE('',#1223);
#1225=ORIENTED_EDGE('',*,*,#1086,.T.);
#1226=ORIENTED_EDGE('',*,*,#576,.T.);
#1227=ORIENTED_EDGE('',*,*,#1214,.T.);
#1228=EDGE_LOOP('',(#1225,#1226,#1227));
#1229=FACE_BOUND('',#1228,.T.);
#1230=ADVANCED_FACE('F1097',(#1229),#1224,.F.);
#1231=CARTESIAN_POINT('',(42.,32.,-5.));
#1232=DIRECTION('',(-1.,0.,0.));
#1233=DIRECTION('',(0.,0.,1.));
#1234=AXIS2_PLACEMENT_3D('',#1231,#1232,#1233);
#1235=CYLINDRICAL_SURFACE('',#1234,4.65620826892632);
#1236=DIRECTION('',(-1.,0.,0.));
#1237=VECTOR('',#1236,1.);
#1238=CARTESIAN_POINT('',(42.,36.6562082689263,-5.));
#1239=LINE('',#1238,#1237);
#1240=EDGE_CURVE('E643',#1013,#810,#1239,.T.);
#1241=ORIENTED_EDGE('',*,*,#1240,.T.);
#1242=ORIENTED_EDGE('',*,*,#811,.T.);
#1243=DIRECTION('',(-1.,0.,0.));
#1244=VECTOR('',#1243,1.);
#1245=CARTESIAN_POINT('',(42.,27.3437917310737,-5.));
#1246=LINE('',#1245,#1244);
#1247=EDGE_CURVE('E652',#1022,#801,#1246,.T.);
#1248=ORIENTED_EDGE('',*,*,#1247,.F.);
#1249=ORIENTED_EDGE('',*,*,#1023,.F.);
#1250=EDGE_LOOP('',(#1241,#1242,#1248,#1249));
#1251=FACE_BOUND('',#1250,.T.);
#1252=ADVANCED_FACE('F752',(#1251),#1235,.F.);
#1253=CARTESIAN_POINT('',(42.,36.6562082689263,-5.));
#1254=DIRECTION('',(0.,1.,0.));
#1255=DIRECTION('',(0.,0.,1.));
#1256=AXIS2_PLACEMENT_3D('',#1253,#1254,#1255);
#1257=PLANE('',#1256);
#1258=DIRECTION('',(-1.,0.,0.));
#1259=VECTOR('',#1258,1.);
#1260=CARTESIAN_POINT('',(42.,36.6562082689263,5.));
#1261=LINE('',#1260,#1259);
#1262=EDGE_CURVE('E745',#1005,#768,#1261,.T.);
#1263=ORIENTED_EDGE('',*,*,#1262,.T.);
#1264=ORIENTED_EDGE('',*,*,#769,.T.);
#1265=DIRECTION('',(1.,0.,0.));
#1266=VECTOR('',#1265,1.);
#1267=CARTESIAN_POINT('',(-2.,36.6562082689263,4.9));
#1268=LINE('',#1267,#1266);
#1269=CARTESIAN_POINT('',(-2.,36.6562082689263,4.9));
#1270=VERTEX_POINT('',#1269);
#1271=EDGE_CURVE('E962',#1270,#760,#1268,.T.);
#1272=ORIENTED_EDGE('',*,*,#1271,.F.);
#1273=DIRECTION('',(0.,0.,1.));
#1274=VECTOR('',#1273,1.);
#1275=CARTESIAN_POINT('',(-2.,36.6562082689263,-4.9));
#1276=LINE('',#1275,#1274);
#1277=CARTESIAN_POINT('',(-2.,36.6562082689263,-4.9));
#1278=VERTEX_POINT('',#1277);
#1279=EDGE_CURVE('E949',#1278,#1270,#1276,.T.);
#1280=ORIENTED_EDGE('',*,*,#1279,.F.);
#1281=DIRECTION('',(1.,0.,0.));
#1282=VECTOR('',#1281,1.);
#1283=CARTESIAN_POINT('',(-2.,36.6562082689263,-4.9));
#1284=LINE('',#1283,#1282);
#1285=EDGE_CURVE('E941',#1278,#744,#1284,.T.);
#1286=ORIENTED_EDGE('',*,*,#1285,.T.);
#1287=ORIENTED_EDGE('',*,*,#813,.T.);
#1288=ORIENTED_EDGE('',*,*,#1240,.F.);
#1289=ORIENTED_EDGE('',*,*,#1014,.F.);
#1290=EDGE_LOOP('',(#1263,#1264,#1272,#1280,#1286,#1287,#1288,#1289));
#1291=FACE_BOUND('',#1290,.T.);
#1292=ADVANCED_FACE('F1001',(#1291),#1257,.F.);
#1293=CARTESIAN_POINT('',(42.,32.,5.));
#1294=DIRECTION('',(-1.,0.,0.));
#1295=DIRECTION('',(0.,0.,1.));
#1296=AXIS2_PLACEMENT_3D('',#1293,#1294,#1295);
#1297=CYLINDRICAL_SURFACE('',#1296,4.65620826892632);
#1298=DIRECTION('',(-1.,0.,0.));
#1299=VECTOR('',#1298,1.);
#1300=CARTESIAN_POINT('',(42.,27.3437917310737,5.));
#1301=LINE('',#1300,#1299);
#1302=EDGE_CURVE('E743',#996,#777,#1301,.T.);
#1303=ORIENTED_EDGE('',*,*,#1302,.T.);
#1304=ORIENTED_EDGE('',*,*,#778,.T.);
#1305=ORIENTED_EDGE('',*,*,#1262,.F.);
#1306=ORIENTED_EDGE('',*,*,#1006,.F.);
#1307=EDGE_LOOP('',(#1303,#1304,#1305,#1306));
#1308=FACE_BOUND('',#1307,.T.);
#1309=ADVANCED_FACE('F1008',(#1308),#1297,.F.);
#1310=CARTESIAN_POINT('',(42.,30.,5.));
#1311=DIRECTION('',(0.,0.,1.));
#1312=DIRECTION('',(0.,-1.,0.));
#1313=AXIS2_PLACEMENT_3D('',#1310,#1311,#1312);
#1314=PLANE('',#1313);
#1315=ORIENTED_EDGE('',*,*,#786,.T.);
#1316=ORIENTED_EDGE('',*,*,#1302,.F.);
#1317=ORIENTED_EDGE('',*,*,#997,.F.);
#1318=ORIENTED_EDGE('',*,*,#965,.T.);
#1319=DIRECTION('',(0.,1.,0.));
#1320=VECTOR('',#1319,1.);
#1321=CARTESIAN_POINT('',(7.,10.,5.));
#1322=LINE('',#1321,#1320);
#1323=CARTESIAN_POINT('',(7.,10.,5.));
#1324=VERTEX_POINT('',#1323);
#1325=EDGE_CURVE('E774',#1324,#954,#1322,.T.);
#1326=ORIENTED_EDGE('',*,*,#1325,.F.);
#1327=DIRECTION('',(-1.,0.,0.));
#1328=VECTOR('',#1327,1.);
#1329=CARTESIAN_POINT('',(7.,10.,5.));
#1330=LINE('',#1329,#1328);
#1331=EDGE_CURVE('E773',#1324,#785,#1330,.T.);
#1332=ORIENTED_EDGE('',*,*,#1331,.T.);
#1333=EDGE_LOOP('',(#1315,#1316,#1317,#1318,#1326,#1332));
#1334=FACE_BOUND('',#1333,.T.);
#1335=ADVANCED_FACE('F1011',(#1334),#1314,.F.);
#1336=CARTESIAN_POINT('',(42.,30.,-5.));
#1337=DIRECTION('',(0.,0.,-1.));
#1338=DIRECTION('',(0.,1.,0.));
#1339=AXIS2_PLACEMENT_3D('',#1336,#1337,#1338);
#1340=PLANE('',#1339);
#1341=ORIENTED_EDGE('',*,*,#802,.T.);
#1342=DIRECTION('',(-1.,0.,0.));
#1343=VECTOR('',#1342,1.);
#1344=CARTESIAN_POINT('',(7.,10.,-5.));
#1345=LINE('',#1344,#1343);
#1346=CARTESIAN_POINT('',(7.,10.,-5.));
#1347=VERTEX_POINT('',#1346);
#1348=EDGE_CURVE('E767',#1347,#793,#1345,.T.);
#1349=ORIENTED_EDGE('',*,*,#1348,.F.);
#1350=DIRECTION('',(0.,-1.,0.));
#1351=VECTOR('',#1350,1.);
#1352=CARTESIAN_POINT('',(7.,23.6718958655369,-5.));
#1353=LINE('',#1352,#1351);
#1354=EDGE_CURVE('E963',#956,#1347,#1353,.T.);
#1355=ORIENTED_EDGE('',*,*,#1354,.F.);
#1356=ORIENTED_EDGE('',*,*,#980,.F.);
#1357=ORIENTED_EDGE('',*,*,#1029,.F.);
#1358=ORIENTED_EDGE('',*,*,#1247,.T.);
#1359=EDGE_LOOP('',(#1341,#1349,#1355,#1356,#1357,#1358));
#1360=FACE_BOUND('',#1359,.T.);
#1361=ADVANCED_FACE('F765',(#1360),#1340,.F.);
#1362=CARTESIAN_POINT('',(7.,32.,-5.));
#1363=DIRECTION('',(-1.,0.,0.));
#1364=DIRECTION('',(0.,0.,1.));
#1365=AXIS2_PLACEMENT_3D('',#1362,#1363,#1364);
#1366=CYLINDRICAL_SURFACE('',#1365,7.5);
#1367=ORIENTED_EDGE('',*,*,#904,.F.);
#1368=DIRECTION('',(-1.,0.,0.));
#1369=VECTOR('',#1368,1.);
#1370=CARTESIAN_POINT('',(7.,38.4951905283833,-8.75));
#1371=LINE('',#1370,#1369);
#1372=EDGE_CURVE('E587',#56,#896,#1371,.T.);
#1373=ORIENTED_EDGE('',*,*,#1372,.F.);
#1374=ORIENTED_EDGE('',*,*,#57,.T.);
#1375=ORIENTED_EDGE('',*,*,#102,.T.);
#1376=EDGE_LOOP('',(#1367,#1373,#1374,#1375));
#1377=FACE_BOUND('',#1376,.T.);
#1378=ADVANCED_FACE('F820',(#1377),#1366,.T.);
#1379=DIRECTION('',(0.707106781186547,0.707106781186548,0.));
#1380=VECTOR('',#1379,1.);
#1381=CARTESIAN_POINT('',(-8.63919182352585,-9.97804313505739,-8.75));
#1382=LINE('',#1381,#1380);
#1383=CARTESIAN_POINT('',(8.3388513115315,7.,-8.75));
#1384=VERTEX_POINT('',#1383);
#1385=EDGE_CURVE('E523',#417,#1384,#1382,.T.);
#1386=ORIENTED_EDGE('',*,*,#1385,.T.);
#1387=DIRECTION('',(1.,0.,0.));
#1388=VECTOR('',#1387,1.);
#1389=CARTESIAN_POINT('',(0.,7.,-8.75));
#1390=LINE('',#1389,#1388);
#1391=CARTESIAN_POINT('',(25.5048094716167,7.00000000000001,-8.75));
#1392=VERTEX_POINT('',#1391);
#1393=EDGE_CURVE('E855',#1384,#1392,#1390,.T.);
#1394=ORIENTED_EDGE('',*,*,#1393,.T.);
#1395=DIRECTION('',(0.,-1.,0.));
#1396=VECTOR('',#1395,1.);
#1397=CARTESIAN_POINT('',(25.5048094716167,7.00000000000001,-8.75));
#1398=LINE('',#1397,#1396);
#1399=EDGE_CURVE('E886',#1392,#425,#1398,.T.);
#1400=ORIENTED_EDGE('',*,*,#1399,.T.);
#1401=ORIENTED_EDGE('',*,*,#426,.F.);
#1402=EDGE_LOOP('',(#1386,#1394,#1400,#1401));
#1403=FACE_BOUND('',#1402,.T.);
#1404=ADVANCED_FACE('F835',(#1403),#80,.F.);
#1405=DIRECTION('',(-1.,0.,0.));
#1406=VECTOR('',#1405,1.);
#1407=CARTESIAN_POINT('',(0.,7.,-18.25));
#1408=LINE('',#1407,#1406);
#1409=CARTESIAN_POINT('',(40.,7.00000000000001,-18.25));
#1410=VERTEX_POINT('',#1409);
#1411=CARTESIAN_POINT('',(8.3388513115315,7.,-18.25));
#1412=VERTEX_POINT('',#1411);
#1413=EDGE_CURVE('E870',#1410,#1412,#1408,.T.);
#1414=ORIENTED_EDGE('',*,*,#1413,.T.);
#1415=DIRECTION('',(-0.707106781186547,-0.707106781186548,0.));
#1416=VECTOR('',#1415,1.);
#1417=CARTESIAN_POINT('',(-8.63919182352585,-9.97804313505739,-18.25));
#1418=LINE('',#1417,#1416);
#1419=EDGE_CURVE('E526',#1412,#415,#1418,.T.);
#1420=ORIENTED_EDGE('',*,*,#1419,.T.);
#1421=ORIENTED_EDGE('',*,*,#457,.F.);
#1422=DIRECTION('',(0.,-1.,0.));
#1423=VECTOR('',#1422,1.);
#1424=CARTESIAN_POINT('',(40.,7.00000000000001,-18.25));
#1425=LINE('',#1424,#1423);
#1426=EDGE_CURVE('E876',#1410,#450,#1425,.T.);
#1427=ORIENTED_EDGE('',*,*,#1426,.F.);
#1428=EDGE_LOOP('',(#1414,#1420,#1421,#1427));
#1429=FACE_BOUND('',#1428,.T.);
#1430=ADVANCED_FACE('F827',(#1429),#111,.F.);
#1431=CARTESIAN_POINT('',(7.,40.,0.));
#1432=DIRECTION('',(0.,-1.,0.));
#1433=DIRECTION('',(0.,0.,-1.));
#1434=AXIS2_PLACEMENT_3D('',#1431,#1432,#1433);
#1435=PLANE('',#1434);
#1436=ORIENTED_EDGE('',*,*,#889,.F.);
#1437=ORIENTED_EDGE('',*,*,#127,.F.);
#1438=ORIENTED_EDGE('',*,*,#71,.T.);
#1439=DIRECTION('',(-1.,0.,0.));
#1440=VECTOR('',#1439,1.);
#1441=CARTESIAN_POINT('',(7.,40.,-8.75));
#1442=LINE('',#1441,#1440);
#1443=EDGE_CURVE('E590',#64,#888,#1442,.T.);
#1444=ORIENTED_EDGE('',*,*,#1443,.T.);
#1445=EDGE_LOOP('',(#1436,#1437,#1438,#1444));
#1446=FACE_BOUND('',#1445,.T.);
#1447=ADVANCED_FACE('F813',(#1446),#1435,.T.);
#1448=CARTESIAN_POINT('',(7.,-25.6172349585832,-8.74999999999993));
#1449=DIRECTION('',(0.,0.,-1.));
#1450=DIRECTION('',(0.,1.,0.));
#1451=AXIS2_PLACEMENT_3D('',#1448,#1449,#1450);
#1452=PLANE('',#1451);
#1453=ORIENTED_EDGE('',*,*,#897,.F.);
#1454=ORIENTED_EDGE('',*,*,#1443,.F.);
#1455=ORIENTED_EDGE('',*,*,#65,.T.);
#1456=ORIENTED_EDGE('',*,*,#1372,.T.);
#1457=EDGE_LOOP('',(#1453,#1454,#1455,#1456));
#1458=FACE_BOUND('',#1457,.T.);
#1459=ADVANCED_FACE('F817',(#1458),#1452,.T.);
#1460=CARTESIAN_POINT('',(7.,32.,5.));
#1461=DIRECTION('',(-1.,0.,0.));
#1462=DIRECTION('',(0.,0.,1.));
#1463=AXIS2_PLACEMENT_3D('',#1460,#1461,#1462);
#1464=CYLINDRICAL_SURFACE('',#1463,7.5);
#1465=ORIENTED_EDGE('',*,*,#831,.T.);
#1466=ORIENTED_EDGE('',*,*,#246,.F.);
#1467=ORIENTED_EDGE('',*,*,#190,.F.);
#1468=DIRECTION('',(-1.,0.,0.));
#1469=VECTOR('',#1468,1.);
#1470=CARTESIAN_POINT('',(7.,38.4951905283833,8.75));
#1471=LINE('',#1470,#1469);
#1472=EDGE_CURVE('E600',#182,#830,#1471,.T.);
#1473=ORIENTED_EDGE('',*,*,#1472,.T.);
#1474=EDGE_LOOP('',(#1465,#1466,#1467,#1473));
#1475=FACE_BOUND('',#1474,.T.);
#1476=ADVANCED_FACE('F844',(#1475),#1464,.T.);
#1477=CARTESIAN_POINT('',(7.,-25.6172349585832,8.74999999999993));
#1478=DIRECTION('',(0.,0.,-1.));
#1479=DIRECTION('',(0.,1.,0.));
#1480=AXIS2_PLACEMENT_3D('',#1477,#1478,#1479);
#1481=PLANE('',#1480);
#1482=ORIENTED_EDGE('',*,*,#839,.T.);
#1483=ORIENTED_EDGE('',*,*,#1472,.F.);
#1484=ORIENTED_EDGE('',*,*,#183,.F.);
#1485=DIRECTION('',(-1.,0.,0.));
#1486=VECTOR('',#1485,1.);
#1487=CARTESIAN_POINT('',(7.,40.,8.75));
#1488=LINE('',#1487,#1486);
#1489=EDGE_CURVE('E803',#174,#838,#1488,.T.);
#1490=ORIENTED_EDGE('',*,*,#1489,.T.);
#1491=EDGE_LOOP('',(#1482,#1483,#1484,#1490));
#1492=FACE_BOUND('',#1491,.T.);
#1493=ADVANCED_FACE('F1036',(#1492),#1481,.F.);
#1494=CARTESIAN_POINT('',(7.,40.,0.));
#1495=DIRECTION('',(0.,1.,0.));
#1496=DIRECTION('',(0.,0.,1.));
#1497=AXIS2_PLACEMENT_3D('',#1494,#1495,#1496);
#1498=PLANE('',#1497);
#1499=ORIENTED_EDGE('',*,*,#845,.T.);
#1500=ORIENTED_EDGE('',*,*,#1489,.F.);
#1501=ORIENTED_EDGE('',*,*,#175,.F.);
#1502=ORIENTED_EDGE('',*,*,#221,.T.);
#1503=EDGE_LOOP('',(#1499,#1500,#1501,#1502));
#1504=FACE_BOUND('',#1503,.T.);
#1505=ADVANCED_FACE('F1039',(#1504),#1498,.F.);
#1506=DIRECTION('',(-0.707106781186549,-0.707106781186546,0.));
#1507=VECTOR('',#1506,1.);
#1508=CARTESIAN_POINT('',(5.33885131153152,4.,18.25));
#1509=LINE('',#1508,#1507);
#1510=CARTESIAN_POINT('',(8.33885131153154,7.,18.25));
#1511=VERTEX_POINT('',#1510);
#1512=EDGE_CURVE('E535',#476,#1511,#1509,.F.);
#1513=ORIENTED_EDGE('',*,*,#1512,.T.);
#1514=DIRECTION('',(-1.,0.,0.));
#1515=VECTOR('',#1514,1.);
#1516=CARTESIAN_POINT('',(0.,7.,18.25));
#1517=LINE('',#1516,#1515);
#1518=CARTESIAN_POINT('',(40.,7.00000000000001,18.25));
#1519=VERTEX_POINT('',#1518);
#1520=EDGE_CURVE('E1765',#1519,#1511,#1517,.T.);
#1521=ORIENTED_EDGE('',*,*,#1520,.F.);
#1522=DIRECTION('',(0.,-1.,0.));
#1523=VECTOR('',#1522,1.);
#1524=CARTESIAN_POINT('',(40.,7.00000000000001,18.25));
#1525=LINE('',#1524,#1523);
#1526=EDGE_CURVE('E1795',#1519,#484,#1525,.T.);
#1527=ORIENTED_EDGE('',*,*,#1526,.T.);
#1528=ORIENTED_EDGE('',*,*,#485,.T.);
#1529=EDGE_LOOP('',(#1513,#1521,#1527,#1528));
#1530=FACE_BOUND('',#1529,.T.);
#1531=ADVANCED_FACE('F1031',(#1530),#199,.T.);
#1532=DIRECTION('',(1.,0.,0.));
#1533=VECTOR('',#1532,1.);
#1534=CARTESIAN_POINT('',(0.,7.,8.75));
#1535=LINE('',#1534,#1533);
#1536=CARTESIAN_POINT('',(8.33885131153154,7.,8.75));
#1537=VERTEX_POINT('',#1536);
#1538=CARTESIAN_POINT('',(25.5048094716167,7.00000000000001,8.75));
#1539=VERTEX_POINT('',#1538);
#1540=EDGE_CURVE('E1761',#1537,#1539,#1535,.T.);
#1541=ORIENTED_EDGE('',*,*,#1540,.F.);
#1542=DIRECTION('',(0.707106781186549,0.707106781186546,0.));
#1543=VECTOR('',#1542,1.);
#1544=CARTESIAN_POINT('',(5.33885131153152,4.,8.75));
#1545=LINE('',#1544,#1543);
#1546=EDGE_CURVE('E532',#1537,#466,#1545,.F.);
#1547=ORIENTED_EDGE('',*,*,#1546,.T.);
#1548=ORIENTED_EDGE('',*,*,#469,.T.);
#1549=DIRECTION('',(0.,-1.,0.));
#1550=VECTOR('',#1549,1.);
#1551=CARTESIAN_POINT('',(25.5048094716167,7.00000000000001,8.75));
#1552=LINE('',#1551,#1550);
#1553=EDGE_CURVE('E889',#1539,#468,#1552,.T.);
#1554=ORIENTED_EDGE('',*,*,#1553,.F.);
#1555=EDGE_LOOP('',(#1541,#1547,#1548,#1554));
#1556=FACE_BOUND('',#1555,.T.);
#1557=ADVANCED_FACE('F1024',(#1556),#230,.T.);
#1558=CARTESIAN_POINT('',(7.,23.6718958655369,-5.));
#1559=DIRECTION('',(-1.,0.,0.));
#1560=DIRECTION('',(0.,0.,1.));
#1561=AXIS2_PLACEMENT_3D('',#1558,#1559,#1560);
#1562=PLANE('',#1561);
#1563=ORIENTED_EDGE('',*,*,#957,.T.);
#1564=ORIENTED_EDGE('',*,*,#1354,.T.);
#1565=DIRECTION('',(0.,0.,1.));
#1566=VECTOR('',#1565,1.);
#1567=CARTESIAN_POINT('',(7.,10.,-5.));
#1568=LINE('',#1567,#1566);
#1569=EDGE_CURVE('E772',#1347,#1324,#1568,.T.);
#1570=ORIENTED_EDGE('',*,*,#1569,.T.);
#1571=ORIENTED_EDGE('',*,*,#1325,.T.);
#1572=EDGE_LOOP('',(#1563,#1564,#1570,#1571));
#1573=FACE_BOUND('',#1572,.T.);
#1574=ADVANCED_FACE('F1021',(#1573),#1562,.T.);
#1575=CARTESIAN_POINT('',(7.,10.,-5.));
#1576=DIRECTION('',(0.,-1.,0.));
#1577=DIRECTION('',(0.,0.,-1.));
#1578=AXIS2_PLACEMENT_3D('',#1575,#1576,#1577);
#1579=PLANE('',#1578);
#1580=ORIENTED_EDGE('',*,*,#794,.T.);
#1581=ORIENTED_EDGE('',*,*,#1331,.F.);
#1582=ORIENTED_EDGE('',*,*,#1569,.F.);
#1583=ORIENTED_EDGE('',*,*,#1348,.T.);
#1584=EDGE_LOOP('',(#1580,#1581,#1582,#1583));
#1585=FACE_BOUND('',#1584,.T.);
#1586=ADVANCED_FACE('F770',(#1585),#1579,.F.);
#1587=CARTESIAN_POINT('',(-2.,36.6562082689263,4.9));
#1588=DIRECTION('',(0.,0.,-1.));
#1589=DIRECTION('',(0.,1.,0.));
#1590=AXIS2_PLACEMENT_3D('',#1587,#1588,#1589);
#1591=PLANE('',#1590);
#1592=ORIENTED_EDGE('',*,*,#761,.T.);
#1593=DIRECTION('',(1.,0.,0.));
#1594=VECTOR('',#1593,1.);
#1595=CARTESIAN_POINT('',(-2.,38.6562082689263,4.9));
#1596=LINE('',#1595,#1594);
#1597=CARTESIAN_POINT('',(-2.,38.6562082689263,4.9));
#1598=VERTEX_POINT('',#1597);
#1599=EDGE_CURVE('E959',#1598,#752,#1596,.T.);
#1600=ORIENTED_EDGE('',*,*,#1599,.F.);
#1601=DIRECTION('',(0.,1.,0.));
#1602=VECTOR('',#1601,1.);
#1603=CARTESIAN_POINT('',(-2.,36.6562082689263,4.9));
#1604=LINE('',#1603,#1602);
#1605=EDGE_CURVE('E989',#1270,#1598,#1604,.T.);
#1606=ORIENTED_EDGE('',*,*,#1605,.F.);
#1607=ORIENTED_EDGE('',*,*,#1271,.T.);
#1608=EDGE_LOOP('',(#1592,#1600,#1606,#1607));
#1609=FACE_BOUND('',#1608,.T.);
#1610=ADVANCED_FACE('F1003',(#1609),#1591,.F.);
#1611=CARTESIAN_POINT('',(-2.,38.6562082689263,4.9));
#1612=DIRECTION('',(0.,-1.,0.));
#1613=DIRECTION('',(0.,0.,-1.));
#1614=AXIS2_PLACEMENT_3D('',#1611,#1612,#1613);
#1615=PLANE('',#1614);
#1616=ORIENTED_EDGE('',*,*,#753,.T.);
#1617=DIRECTION('',(1.,0.,0.));
#1618=VECTOR('',#1617,1.);
#1619=CARTESIAN_POINT('',(-2.,38.6562082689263,-4.9));
#1620=LINE('',#1619,#1618);
#1621=CARTESIAN_POINT('',(-2.,38.6562082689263,-4.9));
#1622=VERTEX_POINT('',#1621);
#1623=EDGE_CURVE('E944',#1622,#742,#1620,.T.);
#1624=ORIENTED_EDGE('',*,*,#1623,.F.);
#1625=DIRECTION('',(0.,0.,-1.));
#1626=VECTOR('',#1625,1.);
#1627=CARTESIAN_POINT('',(-2.,38.6562082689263,4.9));
#1628=LINE('',#1627,#1626);
#1629=EDGE_CURVE('E991',#1598,#1622,#1628,.T.);
#1630=ORIENTED_EDGE('',*,*,#1629,.F.);
#1631=ORIENTED_EDGE('',*,*,#1599,.T.);
#1632=EDGE_LOOP('',(#1616,#1624,#1630,#1631));
#1633=FACE_BOUND('',#1632,.T.);
#1634=ADVANCED_FACE('F1005',(#1633),#1615,.F.);
#1635=CARTESIAN_POINT('',(-2.,38.6562082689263,-4.9));
#1636=DIRECTION('',(0.,0.,1.));
#1637=DIRECTION('',(1.,0.,0.));
#1638=AXIS2_PLACEMENT_3D('',#1635,#1636,#1637);
#1639=PLANE('',#1638);
#1640=ORIENTED_EDGE('',*,*,#745,.T.);
#1641=ORIENTED_EDGE('',*,*,#1285,.F.);
#1642=DIRECTION('',(0.,-1.,0.));
#1643=VECTOR('',#1642,1.);
#1644=CARTESIAN_POINT('',(-2.,38.6562082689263,-4.9));
#1645=LINE('',#1644,#1643);
#1646=EDGE_CURVE('E945',#1622,#1278,#1645,.T.);
#1647=ORIENTED_EDGE('',*,*,#1646,.F.);
#1648=ORIENTED_EDGE('',*,*,#1623,.T.);
#1649=EDGE_LOOP('',(#1640,#1641,#1647,#1648));
#1650=FACE_BOUND('',#1649,.T.);
#1651=ADVANCED_FACE('F1000',(#1650),#1639,.F.);
#1652=CARTESIAN_POINT('',(-2.,36.6562082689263,4.9));
#1653=DIRECTION('',(-1.,0.,0.));
#1654=DIRECTION('',(0.,0.,1.));
#1655=AXIS2_PLACEMENT_3D('',#1652,#1653,#1654);
#1656=PLANE('',#1655);
#1657=ORIENTED_EDGE('',*,*,#1279,.T.);
#1658=ORIENTED_EDGE('',*,*,#1605,.T.);
#1659=ORIENTED_EDGE('',*,*,#1629,.T.);
#1660=ORIENTED_EDGE('',*,*,#1646,.T.);
#1661=EDGE_LOOP('',(#1657,#1658,#1659,#1660));
#1662=FACE_BOUND('',#1661,.T.);
#1663=ADVANCED_FACE('F995',(#1662),#1656,.T.);
#1664=CARTESIAN_POINT('',(-2.,6.11245787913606,-4.9));
#1665=DIRECTION('',(0.,0.,1.));
#1666=DIRECTION('',(1.,0.,0.));
#1667=AXIS2_PLACEMENT_3D('',#1664,#1665,#1666);
#1668=PLANE('',#1667);
#1669=ORIENTED_EDGE('',*,*,#916,.T.);
#1670=DIRECTION('',(1.,0.,0.));
#1671=VECTOR('',#1670,1.);
#1672=CARTESIAN_POINT('',(-2.,6.11245787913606,-4.9));
#1673=LINE('',#1672,#1671);
#1674=CARTESIAN_POINT('',(-2.,6.11245787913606,-4.9));
#1675=VERTEX_POINT('',#1674);
#1676=EDGE_CURVE('E973',#1675,#915,#1673,.T.);
#1677=ORIENTED_EDGE('',*,*,#1676,.F.);
#1678=DIRECTION('',(0.,-1.,0.));
#1679=VECTOR('',#1678,1.);
#1680=CARTESIAN_POINT('',(-2.,6.11245787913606,-4.9));
#1681=LINE('',#1680,#1679);
#1682=CARTESIAN_POINT('',(-2.,8.11245787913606,-4.9));
#1683=VERTEX_POINT('',#1682);
#1684=EDGE_CURVE('E1863',#1683,#1675,#1681,.T.);
#1685=ORIENTED_EDGE('',*,*,#1684,.F.);
#1686=DIRECTION('',(1.,0.,0.));
#1687=VECTOR('',#1686,1.);
#1688=CARTESIAN_POINT('',(-2.,8.11245787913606,-4.9));
#1689=LINE('',#1688,#1687);
#1690=EDGE_CURVE('E1873',#1683,#913,#1689,.T.);
#1691=ORIENTED_EDGE('',*,*,#1690,.T.);
#1692=EDGE_LOOP('',(#1669,#1677,#1685,#1691));
#1693=FACE_BOUND('',#1692,.T.);
#1694=ADVANCED_FACE('F1510',(#1693),#1668,.F.);
#1695=CARTESIAN_POINT('',(-2.,6.11245787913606,4.9));
#1696=DIRECTION('',(0.,1.,0.));
#1697=DIRECTION('',(0.,0.,1.));
#1698=AXIS2_PLACEMENT_3D('',#1695,#1696,#1697);
#1699=PLANE('',#1698);
#1700=ORIENTED_EDGE('',*,*,#938,.T.);
#1701=DIRECTION('',(1.,0.,0.));
#1702=VECTOR('',#1701,1.);
#1703=CARTESIAN_POINT('',(-2.,6.11245787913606,4.9));
#1704=LINE('',#1703,#1702);
#1705=CARTESIAN_POINT('',(-2.,6.11245787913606,4.9));
#1706=VERTEX_POINT('',#1705);
#1707=EDGE_CURVE('E977',#1706,#931,#1704,.T.);
#1708=ORIENTED_EDGE('',*,*,#1707,.F.);
#1709=DIRECTION('',(0.,0.,1.));
#1710=VECTOR('',#1709,1.);
#1711=CARTESIAN_POINT('',(-2.,6.11245787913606,4.9));
#1712=LINE('',#1711,#1710);
#1713=EDGE_CURVE('E1866',#1675,#1706,#1712,.T.);
#1714=ORIENTED_EDGE('',*,*,#1713,.F.);
#1715=ORIENTED_EDGE('',*,*,#1676,.T.);
#1716=EDGE_LOOP('',(#1700,#1708,#1714,#1715));
#1717=FACE_BOUND('',#1716,.T.);
#1718=ADVANCED_FACE('F1500',(#1717),#1699,.F.);
#1719=CARTESIAN_POINT('',(-2.,8.11245787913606,4.9));
#1720=DIRECTION('',(0.,0.,-1.));
#1721=DIRECTION('',(-1.,0.,0.));
#1722=AXIS2_PLACEMENT_3D('',#1719,#1720,#1721);
#1723=PLANE('',#1722);
#1724=ORIENTED_EDGE('',*,*,#932,.T.);
#1725=DIRECTION('',(1.,0.,0.));
#1726=VECTOR('',#1725,1.);
#1727=CARTESIAN_POINT('',(-2.,8.11245787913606,4.9));
#1728=LINE('',#1727,#1726);
#1729=CARTESIAN_POINT('',(-2.,8.11245787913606,4.9));
#1730=VERTEX_POINT('',#1729);
#1731=EDGE_CURVE('E984',#1730,#923,#1728,.T.);
#1732=ORIENTED_EDGE('',*,*,#1731,.F.);
#1733=DIRECTION('',(0.,1.,0.));
#1734=VECTOR('',#1733,1.);
#1735=CARTESIAN_POINT('',(-2.,8.11245787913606,4.9));
#1736=LINE('',#1735,#1734);
#1737=EDGE_CURVE('E1869',#1706,#1730,#1736,.T.);
#1738=ORIENTED_EDGE('',*,*,#1737,.F.);
#1739=ORIENTED_EDGE('',*,*,#1707,.T.);
#1740=EDGE_LOOP('',(#1724,#1732,#1738,#1739));
#1741=FACE_BOUND('',#1740,.T.);
#1742=ADVANCED_FACE('F1490',(#1741),#1723,.F.);
#1743=CARTESIAN_POINT('',(-2.,8.11245787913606,-4.9));
#1744=DIRECTION('',(0.,-1.,0.));
#1745=DIRECTION('',(0.,0.,-1.));
#1746=AXIS2_PLACEMENT_3D('',#1743,#1744,#1745);
#1747=PLANE('',#1746);
#1748=ORIENTED_EDGE('',*,*,#924,.T.);
#1749=ORIENTED_EDGE('',*,*,#1690,.F.);
#1750=DIRECTION('',(0.,0.,-1.));
#1751=VECTOR('',#1750,1.);
#1752=CARTESIAN_POINT('',(-2.,8.11245787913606,-4.9));
#1753=LINE('',#1752,#1751);
#1754=EDGE_CURVE('E1871',#1730,#1683,#1753,.T.);
#1755=ORIENTED_EDGE('',*,*,#1754,.F.);
#1756=ORIENTED_EDGE('',*,*,#1731,.T.);
#1757=EDGE_LOOP('',(#1748,#1749,#1755,#1756));
#1758=FACE_BOUND('',#1757,.T.);
#1759=ADVANCED_FACE('F1480',(#1758),#1747,.F.);
#1760=CARTESIAN_POINT('',(-2.,8.11245787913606,-4.9));
#1761=DIRECTION('',(1.,0.,0.));
#1762=DIRECTION('',(0.,0.,-1.));
#1763=AXIS2_PLACEMENT_3D('',#1760,#1761,#1762);
#1764=PLANE('',#1763);
#1765=ORIENTED_EDGE('',*,*,#1684,.T.);
#1766=ORIENTED_EDGE('',*,*,#1713,.T.);
#1767=ORIENTED_EDGE('',*,*,#1737,.T.);
#1768=ORIENTED_EDGE('',*,*,#1754,.T.);
#1769=EDGE_LOOP('',(#1765,#1766,#1767,#1768));
#1770=FACE_BOUND('',#1769,.T.);
#1771=ADVANCED_FACE('F1339',(#1770),#1764,.F.);
#1772=CARTESIAN_POINT('',(36.6562082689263,42.,-5.));
#1773=DIRECTION('',(-1.,0.,0.));
#1774=DIRECTION('',(0.,-1.,0.));
#1775=AXIS2_PLACEMENT_3D('',#1772,#1773,#1774);
#1776=PLANE('',#1775);
#1777=ORIENTED_EDGE('',*,*,#643,.T.);
#1778=DIRECTION('',(0.,-1.,0.));
#1779=VECTOR('',#1778,1.);
#1780=CARTESIAN_POINT('',(36.6562082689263,42.,-5.));
#1781=LINE('',#1780,#1779);
#1782=EDGE_CURVE('E1828',#632,#319,#1781,.T.);
#1783=ORIENTED_EDGE('',*,*,#1782,.T.);
#1784=ORIENTED_EDGE('',*,*,#320,.F.);
#1785=DIRECTION('',(0.,1.,0.));
#1786=VECTOR('',#1785,1.);
#1787=CARTESIAN_POINT('',(36.6562082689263,-1.99999999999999,-4.9));
#1788=LINE('',#1787,#1786);
#1789=CARTESIAN_POINT('',(36.6562082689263,-1.99999999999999,-4.9));
#1790=VERTEX_POINT('',#1789);
#1791=EDGE_CURVE('E1783',#1790,#311,#1788,.T.);
#1792=ORIENTED_EDGE('',*,*,#1791,.F.);
#1793=DIRECTION('',(0.,0.,1.));
#1794=VECTOR('',#1793,1.);
#1795=CARTESIAN_POINT('',(36.6562082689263,-1.99999999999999,-4.9));
#1796=LINE('',#1795,#1794);
#1797=CARTESIAN_POINT('',(36.6562082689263,-1.99999999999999,4.9));
#1798=VERTEX_POINT('',#1797);
#1799=EDGE_CURVE('E497',#1790,#1798,#1796,.T.);
#1800=ORIENTED_EDGE('',*,*,#1799,.T.);
#1801=DIRECTION('',(0.,1.,0.));
#1802=VECTOR('',#1801,1.);
#1803=CARTESIAN_POINT('',(36.6562082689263,-1.99999999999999,4.9));
#1804=LINE('',#1803,#1802);
#1805=EDGE_CURVE('E509',#1798,#365,#1804,.T.);
#1806=ORIENTED_EDGE('',*,*,#1805,.T.);
#1807=ORIENTED_EDGE('',*,*,#366,.F.);
#1808=DIRECTION('',(0.,-1.,0.));
#1809=VECTOR('',#1808,1.);
#1810=CARTESIAN_POINT('',(36.6562082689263,42.,5.));
#1811=LINE('',#1810,#1809);
#1812=EDGE_CURVE('E1834',#642,#361,#1811,.T.);
#1813=ORIENTED_EDGE('',*,*,#1812,.F.);
#1814=EDGE_LOOP('',(#1777,#1783,#1784,#1792,#1800,#1806,#1807,#1813));
#1815=FACE_BOUND('',#1814,.T.);
#1816=ADVANCED_FACE('F1334',(#1815),#1776,.T.);
#1817=CARTESIAN_POINT('',(32.,42.,-5.));
#1818=DIRECTION('',(0.,-1.,0.));
#1819=DIRECTION('',(1.,0.,0.));
#1820=AXIS2_PLACEMENT_3D('',#1817,#1818,#1819);
#1821=CYLINDRICAL_SURFACE('',#1820,4.65620826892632);
#1822=ORIENTED_EDGE('',*,*,#635,.T.);
#1823=ORIENTED_EDGE('',*,*,#688,.T.);
#1824=ORIENTED_EDGE('',*,*,#329,.F.);
#1825=ORIENTED_EDGE('',*,*,#1782,.F.);
#1826=EDGE_LOOP('',(#1822,#1823,#1824,#1825));
#1827=FACE_BOUND('',#1826,.T.);
#1828=ADVANCED_FACE('F1338',(#1827),#1821,.F.);
#1829=CARTESIAN_POINT('',(32.,42.,5.));
#1830=DIRECTION('',(0.,-1.,0.));
#1831=DIRECTION('',(1.,0.,0.));
#1832=AXIS2_PLACEMENT_3D('',#1829,#1830,#1831);
#1833=CYLINDRICAL_SURFACE('',#1832,4.65620826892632);
#1834=ORIENTED_EDGE('',*,*,#652,.T.);
#1835=ORIENTED_EDGE('',*,*,#1812,.T.);
#1836=ORIENTED_EDGE('',*,*,#362,.F.);
#1837=ORIENTED_EDGE('',*,*,#710,.F.);
#1838=EDGE_LOOP('',(#1834,#1835,#1836,#1837));
#1839=FACE_BOUND('',#1838,.T.);
#1840=ADVANCED_FACE('F1418',(#1839),#1833,.F.);
#1841=CARTESIAN_POINT('',(10.,7.,-5.));
#1842=DIRECTION('',(1.,0.,0.));
#1843=DIRECTION('',(0.,1.,0.));
#1844=AXIS2_PLACEMENT_3D('',#1841,#1842,#1843);
#1845=PLANE('',#1844);
#1846=ORIENTED_EDGE('',*,*,#345,.F.);
#1847=ORIENTED_EDGE('',*,*,#681,.F.);
#1848=DIRECTION('',(0.,0.,1.));
#1849=VECTOR('',#1848,1.);
#1850=CARTESIAN_POINT('',(10.,7.,-5.));
#1851=LINE('',#1850,#1849);
#1852=EDGE_CURVE('E908',#680,#718,#1851,.T.);
#1853=ORIENTED_EDGE('',*,*,#1852,.T.);
#1854=ORIENTED_EDGE('',*,*,#719,.T.);
#1855=EDGE_LOOP('',(#1846,#1847,#1853,#1854));
#1856=FACE_BOUND('',#1855,.T.);
#1857=ADVANCED_FACE('F1408',(#1856),#1845,.T.);
#1858=CARTESIAN_POINT('',(23.6718958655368,7.00000000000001,-5.));
#1859=DIRECTION('',(0.,-1.,0.));
#1860=DIRECTION('',(0.,0.,1.));
#1861=AXIS2_PLACEMENT_3D('',#1858,#1859,#1860);
#1862=PLANE('',#1861);
#1863=ORIENTED_EDGE('',*,*,#725,.F.);
#1864=ORIENTED_EDGE('',*,*,#1852,.F.);
#1865=ORIENTED_EDGE('',*,*,#696,.F.);
#1866=ORIENTED_EDGE('',*,*,#535,.F.);
#1867=EDGE_LOOP('',(#1863,#1864,#1865,#1866));
#1868=FACE_BOUND('',#1867,.T.);
#1869=ADVANCED_FACE('F1399',(#1868),#1862,.T.);
#1870=CARTESIAN_POINT('',(32.,7.00000000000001,-5.));
#1871=DIRECTION('',(0.,-1.,0.));
#1872=DIRECTION('',(1.,0.,0.));
#1873=AXIS2_PLACEMENT_3D('',#1870,#1871,#1872);
#1874=CYLINDRICAL_SURFACE('',#1873,7.5);
#1875=ORIENTED_EDGE('',*,*,#435,.T.);
#1876=ORIENTED_EDGE('',*,*,#1399,.F.);
#1877=CARTESIAN_POINT('',(32.,7.00000000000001,-5.));
#1878=DIRECTION('',(0.,1.,0.));
#1879=DIRECTION('',(0.,0.,1.));
#1880=AXIS2_PLACEMENT_3D('',#1877,#1878,#1879);
#1881=CIRCLE('',#1880,7.5);
#1882=CARTESIAN_POINT('',(38.4951905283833,7.00000000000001,-8.75));
#1883=VERTEX_POINT('',#1882);
#1884=EDGE_CURVE('E869',#1883,#1392,#1881,.T.);
#1885=ORIENTED_EDGE('',*,*,#1884,.F.);
#1886=DIRECTION('',(0.,-1.,0.));
#1887=VECTOR('',#1886,1.);
#1888=CARTESIAN_POINT('',(38.4951905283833,7.00000000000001,-8.75));
#1889=LINE('',#1888,#1887);
#1890=EDGE_CURVE('E898',#1883,#434,#1889,.T.);
#1891=ORIENTED_EDGE('',*,*,#1890,.T.);
#1892=EDGE_LOOP('',(#1875,#1876,#1885,#1891));
#1893=FACE_BOUND('',#1892,.T.);
#1894=ADVANCED_FACE('F1390',(#1893),#1874,.T.);
#1895=CARTESIAN_POINT('',(0.,7.,-8.74999999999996));
#1896=DIRECTION('',(0.,0.,1.));
#1897=DIRECTION('',(1.,0.,0.));
#1898=AXIS2_PLACEMENT_3D('',#1895,#1896,#1897);
#1899=PLANE('',#1898);
#1900=ORIENTED_EDGE('',*,*,#443,.T.);
#1901=ORIENTED_EDGE('',*,*,#1890,.F.);
#1902=DIRECTION('',(-1.,0.,0.));
#1903=VECTOR('',#1902,1.);
#1904=CARTESIAN_POINT('',(0.,7.,-8.74999999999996));
#1905=LINE('',#1904,#1903);
#1906=CARTESIAN_POINT('',(40.,7.00000000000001,-8.75));
#1907=VERTEX_POINT('',#1906);
#1908=EDGE_CURVE('E881',#1907,#1883,#1905,.T.);
#1909=ORIENTED_EDGE('',*,*,#1908,.F.);
#1910=DIRECTION('',(0.,-1.,0.));
#1911=VECTOR('',#1910,1.);
#1912=CARTESIAN_POINT('',(40.,7.00000000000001,-8.75));
#1913=LINE('',#1912,#1911);
#1914=EDGE_CURVE('E901',#1907,#442,#1913,.T.);
#1915=ORIENTED_EDGE('',*,*,#1914,.T.);
#1916=EDGE_LOOP('',(#1900,#1901,#1909,#1915));
#1917=FACE_BOUND('',#1916,.T.);
#1918=ADVANCED_FACE('F1380',(#1917),#1899,.F.);
#1919=CARTESIAN_POINT('',(40.,7.00000000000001,0.));
#1920=DIRECTION('',(1.,0.,0.));
#1921=DIRECTION('',(0.,1.,0.));
#1922=AXIS2_PLACEMENT_3D('',#1919,#1920,#1921);
#1923=PLANE('',#1922);
#1924=ORIENTED_EDGE('',*,*,#451,.T.);
#1925=ORIENTED_EDGE('',*,*,#1914,.F.);
#1926=DIRECTION('',(0.,0.,1.));
#1927=VECTOR('',#1926,1.);
#1928=CARTESIAN_POINT('',(40.,7.00000000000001,0.));
#1929=LINE('',#1928,#1927);
#1930=EDGE_CURVE('E879',#1410,#1907,#1929,.T.);
#1931=ORIENTED_EDGE('',*,*,#1930,.F.);
#1932=ORIENTED_EDGE('',*,*,#1426,.T.);
#1933=EDGE_LOOP('',(#1924,#1925,#1931,#1932));
#1934=FACE_BOUND('',#1933,.T.);
#1935=ADVANCED_FACE('F1180',(#1934),#1923,.F.);
#1936=CARTESIAN_POINT('',(0.,7.,0.));
#1937=DIRECTION('',(0.,-1.,0.));
#1938=DIRECTION('',(0.,0.,1.));
#1939=AXIS2_PLACEMENT_3D('',#1936,#1937,#1938);
#1940=PLANE('',#1939);
#1941=DIRECTION('',(0.,0.,1.));
#1942=VECTOR('',#1941,1.);
#1943=CARTESIAN_POINT('',(8.3388513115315,7.,-24.3860623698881));
#1944=LINE('',#1943,#1942);
#1945=EDGE_CURVE('E569',#1412,#1384,#1944,.T.);
#1946=ORIENTED_EDGE('',*,*,#1945,.F.);
#1947=ORIENTED_EDGE('',*,*,#1413,.F.);
#1948=ORIENTED_EDGE('',*,*,#1930,.T.);
#1949=ORIENTED_EDGE('',*,*,#1908,.T.);
#1950=ORIENTED_EDGE('',*,*,#1884,.T.);
#1951=ORIENTED_EDGE('',*,*,#1393,.F.);
#1952=EDGE_LOOP('',(#1946,#1947,#1948,#1949,#1950,#1951));
#1953=FACE_BOUND('',#1952,.T.);
#1954=ADVANCED_FACE('F864',(#1953),#1940,.T.);
#1955=CARTESIAN_POINT('',(32.,7.00000000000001,5.));
#1956=DIRECTION('',(0.,-1.,0.));
#1957=DIRECTION('',(1.,0.,0.));
#1958=AXIS2_PLACEMENT_3D('',#1955,#1956,#1957);
#1959=CYLINDRICAL_SURFACE('',#1958,7.5);
#1960=ORIENTED_EDGE('',*,*,#508,.F.);
#1961=DIRECTION('',(0.,-1.,0.));
#1962=VECTOR('',#1961,1.);
#1963=CARTESIAN_POINT('',(38.4951905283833,7.00000000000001,8.75));
#1964=LINE('',#1963,#1962);
#1965=CARTESIAN_POINT('',(38.4951905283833,7.00000000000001,8.75));
#1966=VERTEX_POINT('',#1965);
#1967=EDGE_CURVE('E1770',#1966,#500,#1964,.T.);
#1968=ORIENTED_EDGE('',*,*,#1967,.F.);
#1969=CARTESIAN_POINT('',(32.,7.00000000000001,5.));
#1970=DIRECTION('',(0.,-1.,0.));
#1971=DIRECTION('',(0.,0.,-1.));
#1972=AXIS2_PLACEMENT_3D('',#1969,#1970,#1971);
#1973=CIRCLE('',#1972,7.5);
#1974=EDGE_CURVE('E1793',#1966,#1539,#1973,.T.);
#1975=ORIENTED_EDGE('',*,*,#1974,.T.);
#1976=ORIENTED_EDGE('',*,*,#1553,.T.);
#1977=EDGE_LOOP('',(#1960,#1968,#1975,#1976));
#1978=FACE_BOUND('',#1977,.T.);
#1979=ADVANCED_FACE('F1179',(#1978),#1959,.T.);
#1980=CARTESIAN_POINT('',(40.,7.00000000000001,0.));
#1981=DIRECTION('',(-1.,0.,0.));
#1982=DIRECTION('',(0.,-1.,0.));
#1983=AXIS2_PLACEMENT_3D('',#1980,#1981,#1982);
#1984=PLANE('',#1983);
#1985=ORIENTED_EDGE('',*,*,#493,.F.);
#1986=ORIENTED_EDGE('',*,*,#1526,.F.);
#1987=DIRECTION('',(0.,0.,-1.));
#1988=VECTOR('',#1987,1.);
#1989=CARTESIAN_POINT('',(40.,7.00000000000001,0.));
#1990=LINE('',#1989,#1988);
#1991=CARTESIAN_POINT('',(40.,7.00000000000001,8.75));
#1992=VERTEX_POINT('',#1991);
#1993=EDGE_CURVE('E1775',#1519,#1992,#1990,.T.);
#1994=ORIENTED_EDGE('',*,*,#1993,.T.);
#1995=DIRECTION('',(0.,-1.,0.));
#1996=VECTOR('',#1995,1.);
#1997=CARTESIAN_POINT('',(40.,7.00000000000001,8.75));
#1998=LINE('',#1997,#1996);
#1999=EDGE_CURVE('E1773',#1992,#492,#1998,.T.);
#2000=ORIENTED_EDGE('',*,*,#1999,.T.);
#2001=EDGE_LOOP('',(#1985,#1986,#1994,#2000));
#2002=FACE_BOUND('',#2001,.T.);
#2003=ADVANCED_FACE('F1353',(#2002),#1984,.T.);
#2004=CARTESIAN_POINT('',(0.,7.,8.74999999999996));
#2005=DIRECTION('',(0.,0.,1.));
#2006=DIRECTION('',(1.,0.,0.));
#2007=AXIS2_PLACEMENT_3D('',#2004,#2005,#2006);
#2008=PLANE('',#2007);
#2009=ORIENTED_EDGE('',*,*,#501,.F.);
#2010=ORIENTED_EDGE('',*,*,#1999,.F.);
#2011=DIRECTION('',(-1.,0.,0.));
#2012=VECTOR('',#2011,1.);
#2013=CARTESIAN_POINT('',(0.,7.,8.74999999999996));
#2014=LINE('',#2013,#2012);
#2015=EDGE_CURVE('E1804',#1992,#1966,#2014,.T.);
#2016=ORIENTED_EDGE('',*,*,#2015,.T.);
#2017=ORIENTED_EDGE('',*,*,#1967,.T.);
#2018=EDGE_LOOP('',(#2009,#2010,#2016,#2017));
#2019=FACE_BOUND('',#2018,.T.);
#2020=ADVANCED_FACE('F1348',(#2019),#2008,.T.);
#2021=CARTESIAN_POINT('',(0.,7.,0.));
#2022=DIRECTION('',(0.,-1.,0.));
#2023=DIRECTION('',(0.,0.,-1.));
#2024=AXIS2_PLACEMENT_3D('',#2021,#2022,#2023);
#2025=PLANE('',#2024);
#2026=DIRECTION('',(0.,0.,1.));
#2027=VECTOR('',#2026,1.);
#2028=CARTESIAN_POINT('',(8.33885131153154,7.,2.61393763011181));
#2029=LINE('',#2028,#2027);
#2030=EDGE_CURVE('E567',#1537,#1511,#2029,.T.);
#2031=ORIENTED_EDGE('',*,*,#2030,.F.);
#2032=ORIENTED_EDGE('',*,*,#1540,.T.);
#2033=ORIENTED_EDGE('',*,*,#1974,.F.);
#2034=ORIENTED_EDGE('',*,*,#2015,.F.);
#2035=ORIENTED_EDGE('',*,*,#1993,.F.);
#2036=ORIENTED_EDGE('',*,*,#1520,.T.);
#2037=EDGE_LOOP('',(#2031,#2032,#2033,#2034,#2035,#2036));
#2038=FACE_BOUND('',#2037,.T.);
#2039=ADVANCED_FACE('F1326',(#2038),#2025,.T.);
#2040=CARTESIAN_POINT('',(38.6562082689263,-1.99999999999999,-4.9));
#2041=DIRECTION('',(0.,0.,-1.));
#2042=DIRECTION('',(-1.,0.,0.));
#2043=AXIS2_PLACEMENT_3D('',#2040,#2041,#2042);
#2044=PLANE('',#2043);
#2045=ORIENTED_EDGE('',*,*,#312,.F.);
#2046=DIRECTION('',(0.,1.,0.));
#2047=VECTOR('',#2046,1.);
#2048=CARTESIAN_POINT('',(38.6562082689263,-1.99999999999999,-4.9));
#2049=LINE('',#2048,#2047);
#2050=CARTESIAN_POINT('',(38.6562082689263,-1.99999999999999,-4.9));
#2051=VERTEX_POINT('',#2050);
#2052=EDGE_CURVE('E1808',#2051,#303,#2049,.T.);
#2053=ORIENTED_EDGE('',*,*,#2052,.F.);
#2054=DIRECTION('',(-1.,0.,0.));
#2055=VECTOR('',#2054,1.);
#2056=CARTESIAN_POINT('',(38.6562082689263,-1.99999999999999,-4.9));
#2057=LINE('',#2056,#2055);
#2058=EDGE_CURVE('E499',#2051,#1790,#2057,.T.);
#2059=ORIENTED_EDGE('',*,*,#2058,.T.);
#2060=ORIENTED_EDGE('',*,*,#1791,.T.);
#2061=EDGE_LOOP('',(#2045,#2053,#2059,#2060));
#2062=FACE_BOUND('',#2061,.T.);
#2063=ADVANCED_FACE('F1316',(#2062),#2044,.T.);
#2064=CARTESIAN_POINT('',(38.6562082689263,-1.99999999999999,4.9));
#2065=DIRECTION('',(1.,0.,0.));
#2066=DIRECTION('',(0.,1.,0.));
#2067=AXIS2_PLACEMENT_3D('',#2064,#2065,#2066);
#2068=PLANE('',#2067);
#2069=ORIENTED_EDGE('',*,*,#304,.F.);
#2070=DIRECTION('',(0.,1.,0.));
#2071=VECTOR('',#2070,1.);
#2072=CARTESIAN_POINT('',(38.6562082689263,-1.99999999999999,4.9));
#2073=LINE('',#2072,#2071);
#2074=CARTESIAN_POINT('',(38.6562082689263,-1.99999999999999,4.9));
#2075=VERTEX_POINT('',#2074);
#2076=EDGE_CURVE('E1810',#2075,#301,#2073,.T.);
#2077=ORIENTED_EDGE('',*,*,#2076,.F.);
#2078=DIRECTION('',(0.,0.,-1.));
#2079=VECTOR('',#2078,1.);
#2080=CARTESIAN_POINT('',(38.6562082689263,-1.99999999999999,4.9));
#2081=LINE('',#2080,#2079);
#2082=EDGE_CURVE('E503',#2075,#2051,#2081,.T.);
#2083=ORIENTED_EDGE('',*,*,#2082,.T.);
#2084=ORIENTED_EDGE('',*,*,#2052,.T.);
#2085=EDGE_LOOP('',(#2069,#2077,#2083,#2084));
#2086=FACE_BOUND('',#2085,.T.);
#2087=ADVANCED_FACE('F1306',(#2086),#2068,.T.);
#2088=CARTESIAN_POINT('',(36.6562082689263,-1.99999999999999,4.9));
#2089=DIRECTION('',(0.,0.,1.));
#2090=DIRECTION('',(1.,0.,0.));
#2091=AXIS2_PLACEMENT_3D('',#2088,#2089,#2090);
#2092=PLANE('',#2091);
#2093=ORIENTED_EDGE('',*,*,#372,.F.);
#2094=ORIENTED_EDGE('',*,*,#1805,.F.);
#2095=DIRECTION('',(1.,0.,0.));
#2096=VECTOR('',#2095,1.);
#2097=CARTESIAN_POINT('',(36.6562082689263,-1.99999999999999,4.9));
#2098=LINE('',#2097,#2096);
#2099=EDGE_CURVE('E506',#1798,#2075,#2098,.T.);
#2100=ORIENTED_EDGE('',*,*,#2099,.T.);
#2101=ORIENTED_EDGE('',*,*,#2076,.T.);
#2102=EDGE_LOOP('',(#2093,#2094,#2100,#2101));
#2103=FACE_BOUND('',#2102,.T.);
#2104=ADVANCED_FACE('F1296',(#2103),#2092,.T.);
#2105=CARTESIAN_POINT('',(36.6562082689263,-1.99999999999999,4.9));
#2106=DIRECTION('',(0.,-1.,0.));
#2107=DIRECTION('',(0.,0.,1.));
#2108=AXIS2_PLACEMENT_3D('',#2105,#2106,#2107);
#2109=PLANE('',#2108);
#2110=ORIENTED_EDGE('',*,*,#1799,.F.);
#2111=ORIENTED_EDGE('',*,*,#2058,.F.);
#2112=ORIENTED_EDGE('',*,*,#2082,.F.);
#2113=ORIENTED_EDGE('',*,*,#2099,.F.);
#2114=EDGE_LOOP('',(#2110,#2111,#2112,#2113));
#2115=FACE_BOUND('',#2114,.T.);
#2116=ADVANCED_FACE('F1287',(#2115),#2109,.T.);
#2117=CARTESIAN_POINT('',(6.11245787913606,-2.,-4.9));
#2118=DIRECTION('',(0.,0.,-1.));
#2119=DIRECTION('',(-1.,0.,0.));
#2120=AXIS2_PLACEMENT_3D('',#2117,#2118,#2119);
#2121=PLANE('',#2120);
#2122=ORIENTED_EDGE('',*,*,#278,.F.);
#2123=DIRECTION('',(0.,1.,0.));
#2124=VECTOR('',#2123,1.);
#2125=CARTESIAN_POINT('',(8.11245787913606,-2.,-4.9));
#2126=LINE('',#2125,#2124);
#2127=CARTESIAN_POINT('',(8.11245787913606,-2.,-4.9));
#2128=VERTEX_POINT('',#2127);
#2129=EDGE_CURVE('E451',#2128,#269,#2126,.T.);
#2130=ORIENTED_EDGE('',*,*,#2129,.F.);
#2131=DIRECTION('',(-1.,0.,0.));
#2132=VECTOR('',#2131,1.);
#2133=CARTESIAN_POINT('',(6.11245787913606,-2.,-4.9));
#2134=LINE('',#2133,#2132);
#2135=CARTESIAN_POINT('',(6.11245787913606,-2.,-4.9));
#2136=VERTEX_POINT('',#2135);
#2137=EDGE_CURVE('E454',#2128,#2136,#2134,.T.);
#2138=ORIENTED_EDGE('',*,*,#2137,.T.);
#2139=DIRECTION('',(0.,1.,0.));
#2140=VECTOR('',#2139,1.);
#2141=CARTESIAN_POINT('',(6.11245787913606,-2.,-4.9));
#2142=LINE('',#2141,#2140);
#2143=EDGE_CURVE('E482',#2136,#277,#2142,.T.);
#2144=ORIENTED_EDGE('',*,*,#2143,.T.);
#2145=EDGE_LOOP('',(#2122,#2130,#2138,#2144));
#2146=FACE_BOUND('',#2145,.T.);
#2147=ADVANCED_FACE('F453',(#2146),#2121,.T.);
#2148=CARTESIAN_POINT('',(8.11245787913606,-2.,-4.9));
#2149=DIRECTION('',(1.,0.,0.));
#2150=DIRECTION('',(0.,1.,0.));
#2151=AXIS2_PLACEMENT_3D('',#2148,#2149,#2150);
#2152=PLANE('',#2151);
#2153=ORIENTED_EDGE('',*,*,#270,.F.);
#2154=DIRECTION('',(0.,1.,0.));
#2155=VECTOR('',#2154,1.);
#2156=CARTESIAN_POINT('',(8.11245787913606,-2.,4.9));
#2157=LINE('',#2156,#2155);
#2158=CARTESIAN_POINT('',(8.11245787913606,-2.,4.9));
#2159=VERTEX_POINT('',#2158);
#2160=EDGE_CURVE('E463',#2159,#267,#2157,.T.);
#2161=ORIENTED_EDGE('',*,*,#2160,.F.);
#2162=DIRECTION('',(0.,0.,-1.));
#2163=VECTOR('',#2162,1.);
#2164=CARTESIAN_POINT('',(8.11245787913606,-2.,-4.9));
#2165=LINE('',#2164,#2163);
#2166=EDGE_CURVE('E469',#2159,#2128,#2165,.T.);
#2167=ORIENTED_EDGE('',*,*,#2166,.T.);
#2168=ORIENTED_EDGE('',*,*,#2129,.T.);
#2169=EDGE_LOOP('',(#2153,#2161,#2167,#2168));
#2170=FACE_BOUND('',#2169,.T.);
#2171=ADVANCED_FACE('F475',(#2170),#2152,.T.);
#2172=CARTESIAN_POINT('',(8.11245787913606,-2.,4.9));
#2173=DIRECTION('',(0.,0.,1.));
#2174=DIRECTION('',(1.,0.,0.));
#2175=AXIS2_PLACEMENT_3D('',#2172,#2173,#2174);
#2176=PLANE('',#2175);
#2177=ORIENTED_EDGE('',*,*,#292,.F.);
#2178=DIRECTION('',(0.,1.,0.));
#2179=VECTOR('',#2178,1.);
#2180=CARTESIAN_POINT('',(6.11245787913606,-2.,4.9));
#2181=LINE('',#2180,#2179);
#2182=CARTESIAN_POINT('',(6.11245787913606,-2.,4.9));
#2183=VERTEX_POINT('',#2182);
#2184=EDGE_CURVE('E493',#2183,#285,#2181,.T.);
#2185=ORIENTED_EDGE('',*,*,#2184,.F.);
#2186=DIRECTION('',(1.,0.,0.));
#2187=VECTOR('',#2186,1.);
#2188=CARTESIAN_POINT('',(8.11245787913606,-2.,4.9));
#2189=LINE('',#2188,#2187);
#2190=EDGE_CURVE('E476',#2183,#2159,#2189,.T.);
#2191=ORIENTED_EDGE('',*,*,#2190,.T.);
#2192=ORIENTED_EDGE('',*,*,#2160,.T.);
#2193=EDGE_LOOP('',(#2177,#2185,#2191,#2192));
#2194=FACE_BOUND('',#2193,.T.);
#2195=ADVANCED_FACE('F1260',(#2194),#2176,.T.);
#2196=CARTESIAN_POINT('',(6.11245787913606,-2.,4.9));
#2197=DIRECTION('',(-1.,0.,0.));
#2198=DIRECTION('',(0.,-1.,0.));
#2199=AXIS2_PLACEMENT_3D('',#2196,#2197,#2198);
#2200=PLANE('',#2199);
#2201=ORIENTED_EDGE('',*,*,#286,.F.);
#2202=ORIENTED_EDGE('',*,*,#2143,.F.);
#2203=DIRECTION('',(0.,0.,1.));
#2204=VECTOR('',#2203,1.);
#2205=CARTESIAN_POINT('',(6.11245787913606,-2.,4.9));
#2206=LINE('',#2205,#2204);
#2207=EDGE_CURVE('E472',#2136,#2183,#2206,.T.);
#2208=ORIENTED_EDGE('',*,*,#2207,.T.);
#2209=ORIENTED_EDGE('',*,*,#2184,.T.);
#2210=EDGE_LOOP('',(#2201,#2202,#2208,#2209));
#2211=FACE_BOUND('',#2210,.T.);
#2212=ADVANCED_FACE('F1251',(#2211),#2200,.T.);
#2213=CARTESIAN_POINT('',(8.11245787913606,-2.,-4.9));
#2214=DIRECTION('',(0.,1.,0.));
#2215=DIRECTION('',(0.,0.,-1.));
#2216=AXIS2_PLACEMENT_3D('',#2213,#2214,#2215);
#2217=PLANE('',#2216);
#2218=ORIENTED_EDGE('',*,*,#2137,.F.);
#2219=ORIENTED_EDGE('',*,*,#2166,.F.);
#2220=ORIENTED_EDGE('',*,*,#2190,.F.);
#2221=ORIENTED_EDGE('',*,*,#2207,.F.);
#2222=EDGE_LOOP('',(#2218,#2219,#2220,#2221));
#2223=FACE_BOUND('',#2222,.T.);
#2224=ADVANCED_FACE('F467',(#2223),#2217,.F.);
#2225=CARTESIAN_POINT('',(1.33885131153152,0.,21.25));
#2226=DIRECTION('',(0.707106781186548,-0.707106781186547,0.));
#2227=DIRECTION('',(0.707106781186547,0.707106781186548,0.));
#2228=AXIS2_PLACEMENT_3D('',#2225,#2226,#2227);
#2229=PLANE('',#2228);
#2230=ORIENTED_EDGE('',*,*,#1419,.F.);
#2231=ORIENTED_EDGE('',*,*,#1945,.T.);
#2232=ORIENTED_EDGE('',*,*,#1385,.F.);
#2233=ORIENTED_EDGE('',*,*,#418,.F.);
#2234=EDGE_LOOP('',(#2230,#2231,#2232,#2233));
#2235=FACE_BOUND('',#2234,.T.);
#2236=ADVANCED_FACE('F872',(#2235),#2229,.T.);
#2237=CARTESIAN_POINT('',(5.33885131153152,4.,0.));
#2238=DIRECTION('',(-0.707106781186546,0.707106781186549,0.));
#2239=DIRECTION('',(-0.707106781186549,-0.707106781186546,0.));
#2240=AXIS2_PLACEMENT_3D('',#2237,#2238,#2239);
#2241=PLANE('',#2240);
#2242=ORIENTED_EDGE('',*,*,#1512,.F.);
#2243=ORIENTED_EDGE('',*,*,#477,.F.);
#2244=ORIENTED_EDGE('',*,*,#1546,.F.);
#2245=ORIENTED_EDGE('',*,*,#2030,.T.);
#2246=EDGE_LOOP('',(#2242,#2243,#2244,#2245));
#2247=FACE_BOUND('',#2246,.T.);
#2248=ADVANCED_FACE('F1123',(#2247),#2241,.F.);
#2249=CARTESIAN_POINT('',(4.,5.33885131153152,0.));
#2250=DIRECTION('',(0.707106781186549,-0.707106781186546,0.));
#2251=DIRECTION('',(0.707106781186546,0.707106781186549,0.));
#2252=AXIS2_PLACEMENT_3D('',#2249,#2250,#2251);
#2253=PLANE('',#2252);
#2254=ORIENTED_EDGE('',*,*,#118,.F.);
#2255=ORIENTED_EDGE('',*,*,#880,.F.);
#2256=ORIENTED_EDGE('',*,*,#88,.F.);
#2257=ORIENTED_EDGE('',*,*,#40,.F.);
#2258=EDGE_LOOP('',(#2254,#2255,#2256,#2257));
#2259=FACE_BOUND('',#2258,.T.);
#2260=ADVANCED_FACE('F1125',(#2259),#2253,.F.);
#2261=CARTESIAN_POINT('',(0.,1.33885131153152,21.25));
#2262=DIRECTION('',(-0.707106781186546,0.707106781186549,0.));
#2263=DIRECTION('',(-0.707106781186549,-0.707106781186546,0.));
#2264=AXIS2_PLACEMENT_3D('',#2261,#2262,#2263);
#2265=PLANE('',#2264);
#2266=ORIENTED_EDGE('',*,*,#207,.F.);
#2267=ORIENTED_EDGE('',*,*,#159,.F.);
#2268=ORIENTED_EDGE('',*,*,#237,.F.);
#2269=ORIENTED_EDGE('',*,*,#821,.F.);
#2270=EDGE_LOOP('',(#2266,#2267,#2268,#2269));
#2271=FACE_BOUND('',#2270,.T.);
#2272=ADVANCED_FACE('F37',(#2271),#2265,.T.);
#2273=CLOSED_SHELL('',(#75,#106,#137,#194,#225,#256,#512,#554,#669,#700,#731,#942,#984,#1090,
#1112,#1134,#1154,#1174,#1191,#1202,#1219,#1230,#1252,#1292,#1309,#1335,#1361,#1378,#1404,#1430,
#1447,#1459,#1476,#1493,#1505,#1531,#1557,#1574,#1586,#1610,#1634,#1651,#1663,#1694,#1718,#1742,
#1759,#1771,#1816,#1828,#1840,#1857,#1869,#1894,#1918,#1935,#1954,#1979,#2003,#2020,#2039,#2063,
#2087,#2104,#2116,#2147,#2171,#2195,#2212,#2224,#2236,#2248,#2260,#2272));
#2274=MANIFOLD_SOLID_BREP('B2',#2273);
#2275=ADVANCED_BREP_SHAPE_REPRESENTATION('',(#18,#2274),#14);
#2276=SHAPE_DEFINITION_REPRESENTATION(#9,#2275);
ENDSEC;
END-ISO-10303-21;
